# Generated deterministically by seda-macro-lef-normalizer-v1; recipe orfs-asap7-fakeram-m4-v1.
VERSION 5.8 ;
BUSBITCHARS "[]" ;
DIVIDERCHAR "/" ;

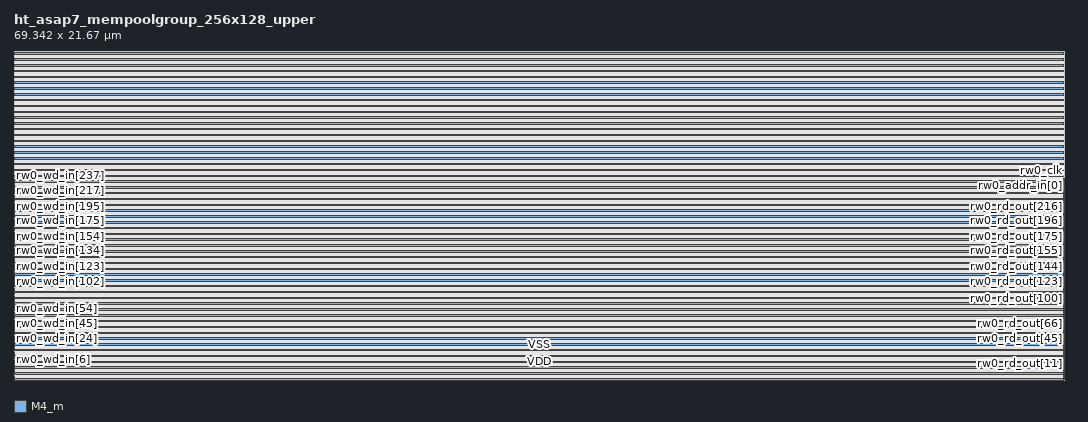
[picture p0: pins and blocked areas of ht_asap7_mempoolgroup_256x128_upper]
MACRO ht_asap7_mempoolgroup_256x128_upper
  FOREIGN ht_asap7_mempoolgroup_256x128_upper 0 0 ;
  CLASS BLOCK ;
  ORIGIN 0 0 ;
  SIZE 69.342 BY 21.67 ;
  SYMMETRY X Y R90 ;
  PIN rw0_wmask_in[0]
    DIRECTION INPUT ;
    USE SIGNAL ;
    SHAPE ABUTMENT ;
    PORT
      LAYER M4_m ;
      RECT 0 0.048 0.024 0.072 ;
    END
  END rw0_wmask_in[0]
  PIN rw0_wmask_in[1]
    DIRECTION INPUT ;
    USE SIGNAL ;
    SHAPE ABUTMENT ;
    PORT
      LAYER M4_m ;
      RECT 0 0.096 0.024 0.12 ;
    END
  END rw0_wmask_in[1]
  PIN rw0_wmask_in[2]
    DIRECTION INPUT ;
    USE SIGNAL ;
    SHAPE ABUTMENT ;
    PORT
      LAYER M4_m ;
      RECT 0 0.144 0.024 0.168 ;
    END
  END rw0_wmask_in[2]
  PIN rw0_wmask_in[3]
    DIRECTION INPUT ;
    USE SIGNAL ;
    SHAPE ABUTMENT ;
    PORT
      LAYER M4_m ;
      RECT 0 0.192 0.024 0.216 ;
    END
  END rw0_wmask_in[3]
  PIN rw0_wmask_in[4]
    DIRECTION INPUT ;
    USE SIGNAL ;
    SHAPE ABUTMENT ;
    PORT
      LAYER M4_m ;
      RECT 0 0.24 0.024 0.264 ;
    END
  END rw0_wmask_in[4]
  PIN rw0_wmask_in[5]
    DIRECTION INPUT ;
    USE SIGNAL ;
    SHAPE ABUTMENT ;
    PORT
      LAYER M4_m ;
      RECT 0 0.288 0.024 0.312 ;
    END
  END rw0_wmask_in[5]
  PIN rw0_wmask_in[6]
    DIRECTION INPUT ;
    USE SIGNAL ;
    SHAPE ABUTMENT ;
    PORT
      LAYER M4_m ;
      RECT 0 0.336 0.024 0.36 ;
    END
  END rw0_wmask_in[6]
  PIN rw0_wmask_in[7]
    DIRECTION INPUT ;
    USE SIGNAL ;
    SHAPE ABUTMENT ;
    PORT
      LAYER M4_m ;
      RECT 0 0.384 0.024 0.408 ;
    END
  END rw0_wmask_in[7]
  PIN rw0_wmask_in[8]
    DIRECTION INPUT ;
    USE SIGNAL ;
    SHAPE ABUTMENT ;
    PORT
      LAYER M4_m ;
      RECT 0 0.432 0.024 0.456 ;
    END
  END rw0_wmask_in[8]
  PIN rw0_wmask_in[9]
    DIRECTION INPUT ;
    USE SIGNAL ;
    SHAPE ABUTMENT ;
    PORT
      LAYER M4_m ;
      RECT 0 0.48 0.024 0.504 ;
    END
  END rw0_wmask_in[9]
  PIN rw0_wmask_in[10]
    DIRECTION INPUT ;
    USE SIGNAL ;
    SHAPE ABUTMENT ;
    PORT
      LAYER M4_m ;
      RECT 0 0.528 0.024 0.552 ;
    END
  END rw0_wmask_in[10]
  PIN rw0_wmask_in[11]
    DIRECTION INPUT ;
    USE SIGNAL ;
    SHAPE ABUTMENT ;
    PORT
      LAYER M4_m ;
      RECT 0 0.576 0.024 0.6 ;
    END
  END rw0_wmask_in[11]
  PIN rw0_wmask_in[12]
    DIRECTION INPUT ;
    USE SIGNAL ;
    SHAPE ABUTMENT ;
    PORT
      LAYER M4_m ;
      RECT 0 0.624 0.024 0.648 ;
    END
  END rw0_wmask_in[12]
  PIN rw0_wmask_in[13]
    DIRECTION INPUT ;
    USE SIGNAL ;
    SHAPE ABUTMENT ;
    PORT
      LAYER M4_m ;
      RECT 0 0.672 0.024 0.696 ;
    END
  END rw0_wmask_in[13]
  PIN rw0_wmask_in[14]
    DIRECTION INPUT ;
    USE SIGNAL ;
    SHAPE ABUTMENT ;
    PORT
      LAYER M4_m ;
      RECT 0 0.72 0.024 0.744 ;
    END
  END rw0_wmask_in[14]
  PIN rw0_wmask_in[15]
    DIRECTION INPUT ;
    USE SIGNAL ;
    SHAPE ABUTMENT ;
    PORT
      LAYER M4_m ;
      RECT 0 0.768 0.024 0.792 ;
    END
  END rw0_wmask_in[15]
  PIN rw0_wmask_in[16]
    DIRECTION INPUT ;
    USE SIGNAL ;
    SHAPE ABUTMENT ;
    PORT
      LAYER M4_m ;
      RECT 0 0.816 0.024 0.84 ;
    END
  END rw0_wmask_in[16]
  PIN rw0_wmask_in[17]
    DIRECTION INPUT ;
    USE SIGNAL ;
    SHAPE ABUTMENT ;
    PORT
      LAYER M4_m ;
      RECT 0 0.864 0.024 0.888 ;
    END
  END rw0_wmask_in[17]
  PIN rw0_wmask_in[18]
    DIRECTION INPUT ;
    USE SIGNAL ;
    SHAPE ABUTMENT ;
    PORT
      LAYER M4_m ;
      RECT 0 0.912 0.024 0.936 ;
    END
  END rw0_wmask_in[18]
  PIN rw0_wmask_in[19]
    DIRECTION INPUT ;
    USE SIGNAL ;
    SHAPE ABUTMENT ;
    PORT
      LAYER M4_m ;
      RECT 0 0.96 0.024 0.984 ;
    END
  END rw0_wmask_in[19]
  PIN rw0_wmask_in[20]
    DIRECTION INPUT ;
    USE SIGNAL ;
    SHAPE ABUTMENT ;
    PORT
      LAYER M4_m ;
      RECT 0 1.008 0.024 1.032 ;
    END
  END rw0_wmask_in[20]
  PIN rw0_wmask_in[21]
    DIRECTION INPUT ;
    USE SIGNAL ;
    SHAPE ABUTMENT ;
    PORT
      LAYER M4_m ;
      RECT 0 1.056 0.024 1.08 ;
    END
  END rw0_wmask_in[21]
  PIN rw0_wmask_in[22]
    DIRECTION INPUT ;
    USE SIGNAL ;
    SHAPE ABUTMENT ;
    PORT
      LAYER M4_m ;
      RECT 0 1.104 0.024 1.128 ;
    END
  END rw0_wmask_in[22]
  PIN rw0_wmask_in[23]
    DIRECTION INPUT ;
    USE SIGNAL ;
    SHAPE ABUTMENT ;
    PORT
      LAYER M4_m ;
      RECT 0 1.152 0.024 1.176 ;
    END
  END rw0_wmask_in[23]
  PIN rw0_wmask_in[24]
    DIRECTION INPUT ;
    USE SIGNAL ;
    SHAPE ABUTMENT ;
    PORT
      LAYER M4_m ;
      RECT 0 1.2 0.024 1.224 ;
    END
  END rw0_wmask_in[24]
  PIN rw0_wmask_in[25]
    DIRECTION INPUT ;
    USE SIGNAL ;
    SHAPE ABUTMENT ;
    PORT
      LAYER M4_m ;
      RECT 0 1.248 0.024 1.272 ;
    END
  END rw0_wmask_in[25]
  PIN rw0_wmask_in[26]
    DIRECTION INPUT ;
    USE SIGNAL ;
    SHAPE ABUTMENT ;
    PORT
      LAYER M4_m ;
      RECT 0 1.296 0.024 1.32 ;
    END
  END rw0_wmask_in[26]
  PIN rw0_wmask_in[27]
    DIRECTION INPUT ;
    USE SIGNAL ;
    SHAPE ABUTMENT ;
    PORT
      LAYER M4_m ;
      RECT 0 1.344 0.024 1.368 ;
    END
  END rw0_wmask_in[27]
  PIN rw0_wmask_in[28]
    DIRECTION INPUT ;
    USE SIGNAL ;
    SHAPE ABUTMENT ;
    PORT
      LAYER M4_m ;
      RECT 0 1.392 0.024 1.416 ;
    END
  END rw0_wmask_in[28]
  PIN rw0_wmask_in[29]
    DIRECTION INPUT ;
    USE SIGNAL ;
    SHAPE ABUTMENT ;
    PORT
      LAYER M4_m ;
      RECT 0 1.44 0.024 1.464 ;
    END
  END rw0_wmask_in[29]
  PIN rw0_wmask_in[30]
    DIRECTION INPUT ;
    USE SIGNAL ;
    SHAPE ABUTMENT ;
    PORT
      LAYER M4_m ;
      RECT 0 1.488 0.024 1.512 ;
    END
  END rw0_wmask_in[30]
  PIN rw0_wmask_in[31]
    DIRECTION INPUT ;
    USE SIGNAL ;
    SHAPE ABUTMENT ;
    PORT
      LAYER M4_m ;
      RECT 0 1.536 0.024 1.56 ;
    END
  END rw0_wmask_in[31]
  PIN rw0_wd_in[0]
    DIRECTION INPUT ;
    USE SIGNAL ;
    SHAPE ABUTMENT ;
    PORT
      LAYER M4_m ;
      RECT 0 1.584 0.024 1.608 ;
    END
  END rw0_wd_in[0]
  PIN rw0_wd_in[1]
    DIRECTION INPUT ;
    USE SIGNAL ;
    SHAPE ABUTMENT ;
    PORT
      LAYER M4_m ;
      RECT 0 1.632 0.024 1.656 ;
    END
  END rw0_wd_in[1]
  PIN rw0_wd_in[2]
    DIRECTION INPUT ;
    USE SIGNAL ;
    SHAPE ABUTMENT ;
    PORT
      LAYER M4_m ;
      RECT 0 1.68 0.024 1.704 ;
    END
  END rw0_wd_in[2]
  PIN rw0_wd_in[3]
    DIRECTION INPUT ;
    USE SIGNAL ;
    SHAPE ABUTMENT ;
    PORT
      LAYER M4_m ;
      RECT 0 1.728 0.024 1.752 ;
    END
  END rw0_wd_in[3]
  PIN rw0_wd_in[4]
    DIRECTION INPUT ;
    USE SIGNAL ;
    SHAPE ABUTMENT ;
    PORT
      LAYER M4_m ;
      RECT 0 1.776 0.024 1.8 ;
    END
  END rw0_wd_in[4]
  PIN rw0_wd_in[5]
    DIRECTION INPUT ;
    USE SIGNAL ;
    SHAPE ABUTMENT ;
    PORT
      LAYER M4_m ;
      RECT 0 1.824 0.024 1.848 ;
    END
  END rw0_wd_in[5]
  PIN rw0_wd_in[6]
    DIRECTION INPUT ;
    USE SIGNAL ;
    SHAPE ABUTMENT ;
    PORT
      LAYER M4_m ;
      RECT 0 1.872 0.024 1.896 ;
    END
  END rw0_wd_in[6]
  PIN rw0_wd_in[7]
    DIRECTION INPUT ;
    USE SIGNAL ;
    SHAPE ABUTMENT ;
    PORT
      LAYER M4_m ;
      RECT 0 1.92 0.024 1.944 ;
    END
  END rw0_wd_in[7]
  PIN rw0_wd_in[8]
    DIRECTION INPUT ;
    USE SIGNAL ;
    SHAPE ABUTMENT ;
    PORT
      LAYER M4_m ;
      RECT 0 1.968 0.024 1.992 ;
    END
  END rw0_wd_in[8]
  PIN rw0_wd_in[9]
    DIRECTION INPUT ;
    USE SIGNAL ;
    SHAPE ABUTMENT ;
    PORT
      LAYER M4_m ;
      RECT 0 2.016 0.024 2.04 ;
    END
  END rw0_wd_in[9]
  PIN rw0_wd_in[10]
    DIRECTION INPUT ;
    USE SIGNAL ;
    SHAPE ABUTMENT ;
    PORT
      LAYER M4_m ;
      RECT 0 2.064 0.024 2.088 ;
    END
  END rw0_wd_in[10]
  PIN rw0_wd_in[11]
    DIRECTION INPUT ;
    USE SIGNAL ;
    SHAPE ABUTMENT ;
    PORT
      LAYER M4_m ;
      RECT 0 2.112 0.024 2.136 ;
    END
  END rw0_wd_in[11]
  PIN rw0_wd_in[12]
    DIRECTION INPUT ;
    USE SIGNAL ;
    SHAPE ABUTMENT ;
    PORT
      LAYER M4_m ;
      RECT 0 2.16 0.024 2.184 ;
    END
  END rw0_wd_in[12]
  PIN rw0_wd_in[13]
    DIRECTION INPUT ;
    USE SIGNAL ;
    SHAPE ABUTMENT ;
    PORT
      LAYER M4_m ;
      RECT 0 2.208 0.024 2.232 ;
    END
  END rw0_wd_in[13]
  PIN rw0_wd_in[14]
    DIRECTION INPUT ;
    USE SIGNAL ;
    SHAPE ABUTMENT ;
    PORT
      LAYER M4_m ;
      RECT 0 2.256 0.024 2.28 ;
    END
  END rw0_wd_in[14]
  PIN rw0_wd_in[15]
    DIRECTION INPUT ;
    USE SIGNAL ;
    SHAPE ABUTMENT ;
    PORT
      LAYER M4_m ;
      RECT 0 2.304 0.024 2.328 ;
    END
  END rw0_wd_in[15]
  PIN rw0_wd_in[16]
    DIRECTION INPUT ;
    USE SIGNAL ;
    SHAPE ABUTMENT ;
    PORT
      LAYER M4_m ;
      RECT 0 2.352 0.024 2.376 ;
    END
  END rw0_wd_in[16]
  PIN rw0_wd_in[17]
    DIRECTION INPUT ;
    USE SIGNAL ;
    SHAPE ABUTMENT ;
    PORT
      LAYER M4_m ;
      RECT 0 2.4 0.024 2.424 ;
    END
  END rw0_wd_in[17]
  PIN rw0_wd_in[18]
    DIRECTION INPUT ;
    USE SIGNAL ;
    SHAPE ABUTMENT ;
    PORT
      LAYER M4_m ;
      RECT 0 2.448 0.024 2.472 ;
    END
  END rw0_wd_in[18]
  PIN rw0_wd_in[19]
    DIRECTION INPUT ;
    USE SIGNAL ;
    SHAPE ABUTMENT ;
    PORT
      LAYER M4_m ;
      RECT 0 2.496 0.024 2.52 ;
    END
  END rw0_wd_in[19]
  PIN rw0_wd_in[20]
    DIRECTION INPUT ;
    USE SIGNAL ;
    SHAPE ABUTMENT ;
    PORT
      LAYER M4_m ;
      RECT 0 2.544 0.024 2.568 ;
    END
  END rw0_wd_in[20]
  PIN rw0_wd_in[21]
    DIRECTION INPUT ;
    USE SIGNAL ;
    SHAPE ABUTMENT ;
    PORT
      LAYER M4_m ;
      RECT 0 2.592 0.024 2.616 ;
    END
  END rw0_wd_in[21]
  PIN rw0_wd_in[22]
    DIRECTION INPUT ;
    USE SIGNAL ;
    SHAPE ABUTMENT ;
    PORT
      LAYER M4_m ;
      RECT 0 2.64 0.024 2.664 ;
    END
  END rw0_wd_in[22]
  PIN rw0_wd_in[23]
    DIRECTION INPUT ;
    USE SIGNAL ;
    SHAPE ABUTMENT ;
    PORT
      LAYER M4_m ;
      RECT 0 2.688 0.024 2.712 ;
    END
  END rw0_wd_in[23]
  PIN rw0_wd_in[24]
    DIRECTION INPUT ;
    USE SIGNAL ;
    SHAPE ABUTMENT ;
    PORT
      LAYER M4_m ;
      RECT 0 2.736 0.024 2.76 ;
    END
  END rw0_wd_in[24]
  PIN rw0_wd_in[25]
    DIRECTION INPUT ;
    USE SIGNAL ;
    SHAPE ABUTMENT ;
    PORT
      LAYER M4_m ;
      RECT 0 2.784 0.024 2.808 ;
    END
  END rw0_wd_in[25]
  PIN rw0_wd_in[26]
    DIRECTION INPUT ;
    USE SIGNAL ;
    SHAPE ABUTMENT ;
    PORT
      LAYER M4_m ;
      RECT 0 2.832 0.024 2.856 ;
    END
  END rw0_wd_in[26]
  PIN rw0_wd_in[27]
    DIRECTION INPUT ;
    USE SIGNAL ;
    SHAPE ABUTMENT ;
    PORT
      LAYER M4_m ;
      RECT 0 2.88 0.024 2.904 ;
    END
  END rw0_wd_in[27]
  PIN rw0_wd_in[28]
    DIRECTION INPUT ;
    USE SIGNAL ;
    SHAPE ABUTMENT ;
    PORT
      LAYER M4_m ;
      RECT 0 2.928 0.024 2.952 ;
    END
  END rw0_wd_in[28]
  PIN rw0_wd_in[29]
    DIRECTION INPUT ;
    USE SIGNAL ;
    SHAPE ABUTMENT ;
    PORT
      LAYER M4_m ;
      RECT 0 2.976 0.024 3 ;
    END
  END rw0_wd_in[29]
  PIN rw0_wd_in[30]
    DIRECTION INPUT ;
    USE SIGNAL ;
    SHAPE ABUTMENT ;
    PORT
      LAYER M4_m ;
      RECT 0 3.024 0.024 3.048 ;
    END
  END rw0_wd_in[30]
  PIN rw0_wd_in[31]
    DIRECTION INPUT ;
    USE SIGNAL ;
    SHAPE ABUTMENT ;
    PORT
      LAYER M4_m ;
      RECT 0 3.072 0.024 3.096 ;
    END
  END rw0_wd_in[31]
  PIN rw0_wd_in[32]
    DIRECTION INPUT ;
    USE SIGNAL ;
    SHAPE ABUTMENT ;
    PORT
      LAYER M4_m ;
      RECT 0 3.12 0.024 3.144 ;
    END
  END rw0_wd_in[32]
  PIN rw0_wd_in[33]
    DIRECTION INPUT ;
    USE SIGNAL ;
    SHAPE ABUTMENT ;
    PORT
      LAYER M4_m ;
      RECT 0 3.168 0.024 3.192 ;
    END
  END rw0_wd_in[33]
  PIN rw0_wd_in[34]
    DIRECTION INPUT ;
    USE SIGNAL ;
    SHAPE ABUTMENT ;
    PORT
      LAYER M4_m ;
      RECT 0 3.216 0.024 3.24 ;
    END
  END rw0_wd_in[34]
  PIN rw0_wd_in[35]
    DIRECTION INPUT ;
    USE SIGNAL ;
    SHAPE ABUTMENT ;
    PORT
      LAYER M4_m ;
      RECT 0 3.264 0.024 3.288 ;
    END
  END rw0_wd_in[35]
  PIN rw0_wd_in[36]
    DIRECTION INPUT ;
    USE SIGNAL ;
    SHAPE ABUTMENT ;
    PORT
      LAYER M4_m ;
      RECT 0 3.312 0.024 3.336 ;
    END
  END rw0_wd_in[36]
  PIN rw0_wd_in[37]
    DIRECTION INPUT ;
    USE SIGNAL ;
    SHAPE ABUTMENT ;
    PORT
      LAYER M4_m ;
      RECT 0 3.36 0.024 3.384 ;
    END
  END rw0_wd_in[37]
  PIN rw0_wd_in[38]
    DIRECTION INPUT ;
    USE SIGNAL ;
    SHAPE ABUTMENT ;
    PORT
      LAYER M4_m ;
      RECT 0 3.408 0.024 3.432 ;
    END
  END rw0_wd_in[38]
  PIN rw0_wd_in[39]
    DIRECTION INPUT ;
    USE SIGNAL ;
    SHAPE ABUTMENT ;
    PORT
      LAYER M4_m ;
      RECT 0 3.456 0.024 3.48 ;
    END
  END rw0_wd_in[39]
  PIN rw0_wd_in[40]
    DIRECTION INPUT ;
    USE SIGNAL ;
    SHAPE ABUTMENT ;
    PORT
      LAYER M4_m ;
      RECT 0 3.504 0.024 3.528 ;
    END
  END rw0_wd_in[40]
  PIN rw0_wd_in[41]
    DIRECTION INPUT ;
    USE SIGNAL ;
    SHAPE ABUTMENT ;
    PORT
      LAYER M4_m ;
      RECT 0 3.552 0.024 3.576 ;
    END
  END rw0_wd_in[41]
  PIN rw0_wd_in[42]
    DIRECTION INPUT ;
    USE SIGNAL ;
    SHAPE ABUTMENT ;
    PORT
      LAYER M4_m ;
      RECT 0 3.6 0.024 3.624 ;
    END
  END rw0_wd_in[42]
  PIN rw0_wd_in[43]
    DIRECTION INPUT ;
    USE SIGNAL ;
    SHAPE ABUTMENT ;
    PORT
      LAYER M4_m ;
      RECT 0 3.648 0.024 3.672 ;
    END
  END rw0_wd_in[43]
  PIN rw0_wd_in[44]
    DIRECTION INPUT ;
    USE SIGNAL ;
    SHAPE ABUTMENT ;
    PORT
      LAYER M4_m ;
      RECT 0 3.696 0.024 3.72 ;
    END
  END rw0_wd_in[44]
  PIN rw0_wd_in[45]
    DIRECTION INPUT ;
    USE SIGNAL ;
    SHAPE ABUTMENT ;
    PORT
      LAYER M4_m ;
      RECT 0 3.744 0.024 3.768 ;
    END
  END rw0_wd_in[45]
  PIN rw0_wd_in[46]
    DIRECTION INPUT ;
    USE SIGNAL ;
    SHAPE ABUTMENT ;
    PORT
      LAYER M4_m ;
      RECT 0 3.792 0.024 3.816 ;
    END
  END rw0_wd_in[46]
  PIN rw0_wd_in[47]
    DIRECTION INPUT ;
    USE SIGNAL ;
    SHAPE ABUTMENT ;
    PORT
      LAYER M4_m ;
      RECT 0 3.84 0.024 3.864 ;
    END
  END rw0_wd_in[47]
  PIN rw0_wd_in[48]
    DIRECTION INPUT ;
    USE SIGNAL ;
    SHAPE ABUTMENT ;
    PORT
      LAYER M4_m ;
      RECT 0 3.888 0.024 3.912 ;
    END
  END rw0_wd_in[48]
  PIN rw0_wd_in[49]
    DIRECTION INPUT ;
    USE SIGNAL ;
    SHAPE ABUTMENT ;
    PORT
      LAYER M4_m ;
      RECT 0 3.936 0.024 3.96 ;
    END
  END rw0_wd_in[49]
  PIN rw0_wd_in[50]
    DIRECTION INPUT ;
    USE SIGNAL ;
    SHAPE ABUTMENT ;
    PORT
      LAYER M4_m ;
      RECT 0 3.984 0.024 4.008 ;
    END
  END rw0_wd_in[50]
  PIN rw0_wd_in[51]
    DIRECTION INPUT ;
    USE SIGNAL ;
    SHAPE ABUTMENT ;
    PORT
      LAYER M4_m ;
      RECT 0 4.032 0.024 4.056 ;
    END
  END rw0_wd_in[51]
  PIN rw0_wd_in[52]
    DIRECTION INPUT ;
    USE SIGNAL ;
    SHAPE ABUTMENT ;
    PORT
      LAYER M4_m ;
      RECT 0 4.08 0.024 4.104 ;
    END
  END rw0_wd_in[52]
  PIN rw0_wd_in[53]
    DIRECTION INPUT ;
    USE SIGNAL ;
    SHAPE ABUTMENT ;
    PORT
      LAYER M4_m ;
      RECT 0 4.128 0.024 4.152 ;
    END
  END rw0_wd_in[53]
  PIN rw0_wd_in[54]
    DIRECTION INPUT ;
    USE SIGNAL ;
    SHAPE ABUTMENT ;
    PORT
      LAYER M4_m ;
      RECT 0 4.176 0.024 4.2 ;
    END
  END rw0_wd_in[54]
  PIN rw0_wd_in[55]
    DIRECTION INPUT ;
    USE SIGNAL ;
    SHAPE ABUTMENT ;
    PORT
      LAYER M4_m ;
      RECT 0 4.224 0.024 4.248 ;
    END
  END rw0_wd_in[55]
  PIN rw0_wd_in[56]
    DIRECTION INPUT ;
    USE SIGNAL ;
    SHAPE ABUTMENT ;
    PORT
      LAYER M4_m ;
      RECT 0 4.272 0.024 4.296 ;
    END
  END rw0_wd_in[56]
  PIN rw0_wd_in[57]
    DIRECTION INPUT ;
    USE SIGNAL ;
    SHAPE ABUTMENT ;
    PORT
      LAYER M4_m ;
      RECT 0 4.32 0.024 4.344 ;
    END
  END rw0_wd_in[57]
  PIN rw0_wd_in[58]
    DIRECTION INPUT ;
    USE SIGNAL ;
    SHAPE ABUTMENT ;
    PORT
      LAYER M4_m ;
      RECT 0 4.368 0.024 4.392 ;
    END
  END rw0_wd_in[58]
  PIN rw0_wd_in[59]
    DIRECTION INPUT ;
    USE SIGNAL ;
    SHAPE ABUTMENT ;
    PORT
      LAYER M4_m ;
      RECT 0 4.416 0.024 4.44 ;
    END
  END rw0_wd_in[59]
  PIN rw0_wd_in[60]
    DIRECTION INPUT ;
    USE SIGNAL ;
    SHAPE ABUTMENT ;
    PORT
      LAYER M4_m ;
      RECT 0 4.464 0.024 4.488 ;
    END
  END rw0_wd_in[60]
  PIN rw0_wd_in[61]
    DIRECTION INPUT ;
    USE SIGNAL ;
    SHAPE ABUTMENT ;
    PORT
      LAYER M4_m ;
      RECT 0 4.512 0.024 4.536 ;
    END
  END rw0_wd_in[61]
  PIN rw0_wd_in[62]
    DIRECTION INPUT ;
    USE SIGNAL ;
    SHAPE ABUTMENT ;
    PORT
      LAYER M4_m ;
      RECT 0 4.56 0.024 4.584 ;
    END
  END rw0_wd_in[62]
  PIN rw0_wd_in[63]
    DIRECTION INPUT ;
    USE SIGNAL ;
    SHAPE ABUTMENT ;
    PORT
      LAYER M4_m ;
      RECT 0 4.608 0.024 4.632 ;
    END
  END rw0_wd_in[63]
  PIN rw0_wd_in[64]
    DIRECTION INPUT ;
    USE SIGNAL ;
    SHAPE ABUTMENT ;
    PORT
      LAYER M4_m ;
      RECT 0 4.656 0.024 4.68 ;
    END
  END rw0_wd_in[64]
  PIN rw0_wd_in[65]
    DIRECTION INPUT ;
    USE SIGNAL ;
    SHAPE ABUTMENT ;
    PORT
      LAYER M4_m ;
      RECT 0 4.704 0.024 4.728 ;
    END
  END rw0_wd_in[65]
  PIN rw0_wd_in[66]
    DIRECTION INPUT ;
    USE SIGNAL ;
    SHAPE ABUTMENT ;
    PORT
      LAYER M4_m ;
      RECT 0 4.752 0.024 4.776 ;
    END
  END rw0_wd_in[66]
  PIN rw0_wd_in[67]
    DIRECTION INPUT ;
    USE SIGNAL ;
    SHAPE ABUTMENT ;
    PORT
      LAYER M4_m ;
      RECT 0 4.8 0.024 4.824 ;
    END
  END rw0_wd_in[67]
  PIN rw0_wd_in[68]
    DIRECTION INPUT ;
    USE SIGNAL ;
    SHAPE ABUTMENT ;
    PORT
      LAYER M4_m ;
      RECT 0 4.848 0.024 4.872 ;
    END
  END rw0_wd_in[68]
  PIN rw0_wd_in[69]
    DIRECTION INPUT ;
    USE SIGNAL ;
    SHAPE ABUTMENT ;
    PORT
      LAYER M4_m ;
      RECT 0 4.896 0.024 4.92 ;
    END
  END rw0_wd_in[69]
  PIN rw0_wd_in[70]
    DIRECTION INPUT ;
    USE SIGNAL ;
    SHAPE ABUTMENT ;
    PORT
      LAYER M4_m ;
      RECT 0 4.944 0.024 4.968 ;
    END
  END rw0_wd_in[70]
  PIN rw0_wd_in[71]
    DIRECTION INPUT ;
    USE SIGNAL ;
    SHAPE ABUTMENT ;
    PORT
      LAYER M4_m ;
      RECT 0 4.992 0.024 5.016 ;
    END
  END rw0_wd_in[71]
  PIN rw0_wd_in[72]
    DIRECTION INPUT ;
    USE SIGNAL ;
    SHAPE ABUTMENT ;
    PORT
      LAYER M4_m ;
      RECT 0 5.04 0.024 5.064 ;
    END
  END rw0_wd_in[72]
  PIN rw0_wd_in[73]
    DIRECTION INPUT ;
    USE SIGNAL ;
    SHAPE ABUTMENT ;
    PORT
      LAYER M4_m ;
      RECT 0 5.088 0.024 5.112 ;
    END
  END rw0_wd_in[73]
  PIN rw0_wd_in[74]
    DIRECTION INPUT ;
    USE SIGNAL ;
    SHAPE ABUTMENT ;
    PORT
      LAYER M4_m ;
      RECT 0 5.136 0.024 5.16 ;
    END
  END rw0_wd_in[74]
  PIN rw0_wd_in[75]
    DIRECTION INPUT ;
    USE SIGNAL ;
    SHAPE ABUTMENT ;
    PORT
      LAYER M4_m ;
      RECT 0 5.184 0.024 5.208 ;
    END
  END rw0_wd_in[75]
  PIN rw0_wd_in[76]
    DIRECTION INPUT ;
    USE SIGNAL ;
    SHAPE ABUTMENT ;
    PORT
      LAYER M4_m ;
      RECT 0 5.232 0.024 5.256 ;
    END
  END rw0_wd_in[76]
  PIN rw0_wd_in[77]
    DIRECTION INPUT ;
    USE SIGNAL ;
    SHAPE ABUTMENT ;
    PORT
      LAYER M4_m ;
      RECT 0 5.28 0.024 5.304 ;
    END
  END rw0_wd_in[77]
  PIN rw0_wd_in[78]
    DIRECTION INPUT ;
    USE SIGNAL ;
    SHAPE ABUTMENT ;
    PORT
      LAYER M4_m ;
      RECT 0 5.328 0.024 5.352 ;
    END
  END rw0_wd_in[78]
  PIN rw0_wd_in[79]
    DIRECTION INPUT ;
    USE SIGNAL ;
    SHAPE ABUTMENT ;
    PORT
      LAYER M4_m ;
      RECT 0 5.376 0.024 5.4 ;
    END
  END rw0_wd_in[79]
  PIN rw0_wd_in[80]
    DIRECTION INPUT ;
    USE SIGNAL ;
    SHAPE ABUTMENT ;
    PORT
      LAYER M4_m ;
      RECT 0 5.424 0.024 5.448 ;
    END
  END rw0_wd_in[80]
  PIN rw0_wd_in[81]
    DIRECTION INPUT ;
    USE SIGNAL ;
    SHAPE ABUTMENT ;
    PORT
      LAYER M4_m ;
      RECT 0 5.472 0.024 5.496 ;
    END
  END rw0_wd_in[81]
  PIN rw0_wd_in[82]
    DIRECTION INPUT ;
    USE SIGNAL ;
    SHAPE ABUTMENT ;
    PORT
      LAYER M4_m ;
      RECT 0 5.52 0.024 5.544 ;
    END
  END rw0_wd_in[82]
  PIN rw0_wd_in[83]
    DIRECTION INPUT ;
    USE SIGNAL ;
    SHAPE ABUTMENT ;
    PORT
      LAYER M4_m ;
      RECT 0 5.568 0.024 5.592 ;
    END
  END rw0_wd_in[83]
  PIN rw0_wd_in[84]
    DIRECTION INPUT ;
    USE SIGNAL ;
    SHAPE ABUTMENT ;
    PORT
      LAYER M4_m ;
      RECT 0 5.616 0.024 5.64 ;
    END
  END rw0_wd_in[84]
  PIN rw0_wd_in[85]
    DIRECTION INPUT ;
    USE SIGNAL ;
    SHAPE ABUTMENT ;
    PORT
      LAYER M4_m ;
      RECT 0 5.664 0.024 5.688 ;
    END
  END rw0_wd_in[85]
  PIN rw0_wd_in[86]
    DIRECTION INPUT ;
    USE SIGNAL ;
    SHAPE ABUTMENT ;
    PORT
      LAYER M4_m ;
      RECT 0 5.712 0.024 5.736 ;
    END
  END rw0_wd_in[86]
  PIN rw0_wd_in[87]
    DIRECTION INPUT ;
    USE SIGNAL ;
    SHAPE ABUTMENT ;
    PORT
      LAYER M4_m ;
      RECT 0 5.76 0.024 5.784 ;
    END
  END rw0_wd_in[87]
  PIN rw0_wd_in[88]
    DIRECTION INPUT ;
    USE SIGNAL ;
    SHAPE ABUTMENT ;
    PORT
      LAYER M4_m ;
      RECT 0 5.808 0.024 5.832 ;
    END
  END rw0_wd_in[88]
  PIN rw0_wd_in[89]
    DIRECTION INPUT ;
    USE SIGNAL ;
    SHAPE ABUTMENT ;
    PORT
      LAYER M4_m ;
      RECT 0 5.856 0.024 5.88 ;
    END
  END rw0_wd_in[89]
  PIN rw0_wd_in[90]
    DIRECTION INPUT ;
    USE SIGNAL ;
    SHAPE ABUTMENT ;
    PORT
      LAYER M4_m ;
      RECT 0 5.904 0.024 5.928 ;
    END
  END rw0_wd_in[90]
  PIN rw0_wd_in[91]
    DIRECTION INPUT ;
    USE SIGNAL ;
    SHAPE ABUTMENT ;
    PORT
      LAYER M4_m ;
      RECT 0 5.952 0.024 5.976 ;
    END
  END rw0_wd_in[91]
  PIN rw0_wd_in[92]
    DIRECTION INPUT ;
    USE SIGNAL ;
    SHAPE ABUTMENT ;
    PORT
      LAYER M4_m ;
      RECT 0 6 0.024 6.024 ;
    END
  END rw0_wd_in[92]
  PIN rw0_wd_in[93]
    DIRECTION INPUT ;
    USE SIGNAL ;
    SHAPE ABUTMENT ;
    PORT
      LAYER M4_m ;
      RECT 0 6.048 0.024 6.072 ;
    END
  END rw0_wd_in[93]
  PIN rw0_wd_in[94]
    DIRECTION INPUT ;
    USE SIGNAL ;
    SHAPE ABUTMENT ;
    PORT
      LAYER M4_m ;
      RECT 0 6.096 0.024 6.12 ;
    END
  END rw0_wd_in[94]
  PIN rw0_wd_in[95]
    DIRECTION INPUT ;
    USE SIGNAL ;
    SHAPE ABUTMENT ;
    PORT
      LAYER M4_m ;
      RECT 0 6.144 0.024 6.168 ;
    END
  END rw0_wd_in[95]
  PIN rw0_wd_in[96]
    DIRECTION INPUT ;
    USE SIGNAL ;
    SHAPE ABUTMENT ;
    PORT
      LAYER M4_m ;
      RECT 0 6.192 0.024 6.216 ;
    END
  END rw0_wd_in[96]
  PIN rw0_wd_in[97]
    DIRECTION INPUT ;
    USE SIGNAL ;
    SHAPE ABUTMENT ;
    PORT
      LAYER M4_m ;
      RECT 0 6.24 0.024 6.264 ;
    END
  END rw0_wd_in[97]
  PIN rw0_wd_in[98]
    DIRECTION INPUT ;
    USE SIGNAL ;
    SHAPE ABUTMENT ;
    PORT
      LAYER M4_m ;
      RECT 0 6.288 0.024 6.312 ;
    END
  END rw0_wd_in[98]
  PIN rw0_wd_in[99]
    DIRECTION INPUT ;
    USE SIGNAL ;
    SHAPE ABUTMENT ;
    PORT
      LAYER M4_m ;
      RECT 0 6.336 0.024 6.36 ;
    END
  END rw0_wd_in[99]
  PIN rw0_wd_in[100]
    DIRECTION INPUT ;
    USE SIGNAL ;
    SHAPE ABUTMENT ;
    PORT
      LAYER M4_m ;
      RECT 0 6.384 0.024 6.408 ;
    END
  END rw0_wd_in[100]
  PIN rw0_wd_in[101]
    DIRECTION INPUT ;
    USE SIGNAL ;
    SHAPE ABUTMENT ;
    PORT
      LAYER M4_m ;
      RECT 0 6.432 0.024 6.456 ;
    END
  END rw0_wd_in[101]
  PIN rw0_wd_in[102]
    DIRECTION INPUT ;
    USE SIGNAL ;
    SHAPE ABUTMENT ;
    PORT
      LAYER M4_m ;
      RECT 0 6.48 0.024 6.504 ;
    END
  END rw0_wd_in[102]
  PIN rw0_wd_in[103]
    DIRECTION INPUT ;
    USE SIGNAL ;
    SHAPE ABUTMENT ;
    PORT
      LAYER M4_m ;
      RECT 0 6.528 0.024 6.552 ;
    END
  END rw0_wd_in[103]
  PIN rw0_wd_in[104]
    DIRECTION INPUT ;
    USE SIGNAL ;
    SHAPE ABUTMENT ;
    PORT
      LAYER M4_m ;
      RECT 0 6.576 0.024 6.6 ;
    END
  END rw0_wd_in[104]
  PIN rw0_wd_in[105]
    DIRECTION INPUT ;
    USE SIGNAL ;
    SHAPE ABUTMENT ;
    PORT
      LAYER M4_m ;
      RECT 0 6.624 0.024 6.648 ;
    END
  END rw0_wd_in[105]
  PIN rw0_wd_in[106]
    DIRECTION INPUT ;
    USE SIGNAL ;
    SHAPE ABUTMENT ;
    PORT
      LAYER M4_m ;
      RECT 0 6.672 0.024 6.696 ;
    END
  END rw0_wd_in[106]
  PIN rw0_wd_in[107]
    DIRECTION INPUT ;
    USE SIGNAL ;
    SHAPE ABUTMENT ;
    PORT
      LAYER M4_m ;
      RECT 0 6.72 0.024 6.744 ;
    END
  END rw0_wd_in[107]
  PIN rw0_wd_in[108]
    DIRECTION INPUT ;
    USE SIGNAL ;
    SHAPE ABUTMENT ;
    PORT
      LAYER M4_m ;
      RECT 0 6.768 0.024 6.792 ;
    END
  END rw0_wd_in[108]
  PIN rw0_wd_in[109]
    DIRECTION INPUT ;
    USE SIGNAL ;
    SHAPE ABUTMENT ;
    PORT
      LAYER M4_m ;
      RECT 0 6.816 0.024 6.84 ;
    END
  END rw0_wd_in[109]
  PIN rw0_wd_in[110]
    DIRECTION INPUT ;
    USE SIGNAL ;
    SHAPE ABUTMENT ;
    PORT
      LAYER M4_m ;
      RECT 0 6.864 0.024 6.888 ;
    END
  END rw0_wd_in[110]
  PIN rw0_wd_in[111]
    DIRECTION INPUT ;
    USE SIGNAL ;
    SHAPE ABUTMENT ;
    PORT
      LAYER M4_m ;
      RECT 0 6.912 0.024 6.936 ;
    END
  END rw0_wd_in[111]
  PIN rw0_wd_in[112]
    DIRECTION INPUT ;
    USE SIGNAL ;
    SHAPE ABUTMENT ;
    PORT
      LAYER M4_m ;
      RECT 0 6.96 0.024 6.984 ;
    END
  END rw0_wd_in[112]
  PIN rw0_wd_in[113]
    DIRECTION INPUT ;
    USE SIGNAL ;
    SHAPE ABUTMENT ;
    PORT
      LAYER M4_m ;
      RECT 0 7.008 0.024 7.032 ;
    END
  END rw0_wd_in[113]
  PIN rw0_wd_in[114]
    DIRECTION INPUT ;
    USE SIGNAL ;
    SHAPE ABUTMENT ;
    PORT
      LAYER M4_m ;
      RECT 0 7.056 0.024 7.08 ;
    END
  END rw0_wd_in[114]
  PIN rw0_wd_in[115]
    DIRECTION INPUT ;
    USE SIGNAL ;
    SHAPE ABUTMENT ;
    PORT
      LAYER M4_m ;
      RECT 0 7.104 0.024 7.128 ;
    END
  END rw0_wd_in[115]
  PIN rw0_wd_in[116]
    DIRECTION INPUT ;
    USE SIGNAL ;
    SHAPE ABUTMENT ;
    PORT
      LAYER M4_m ;
      RECT 0 7.152 0.024 7.176 ;
    END
  END rw0_wd_in[116]
  PIN rw0_wd_in[117]
    DIRECTION INPUT ;
    USE SIGNAL ;
    SHAPE ABUTMENT ;
    PORT
      LAYER M4_m ;
      RECT 0 7.2 0.024 7.224 ;
    END
  END rw0_wd_in[117]
  PIN rw0_wd_in[118]
    DIRECTION INPUT ;
    USE SIGNAL ;
    SHAPE ABUTMENT ;
    PORT
      LAYER M4_m ;
      RECT 0 7.248 0.024 7.272 ;
    END
  END rw0_wd_in[118]
  PIN rw0_wd_in[119]
    DIRECTION INPUT ;
    USE SIGNAL ;
    SHAPE ABUTMENT ;
    PORT
      LAYER M4_m ;
      RECT 0 7.296 0.024 7.32 ;
    END
  END rw0_wd_in[119]
  PIN rw0_wd_in[120]
    DIRECTION INPUT ;
    USE SIGNAL ;
    SHAPE ABUTMENT ;
    PORT
      LAYER M4_m ;
      RECT 0 7.344 0.024 7.368 ;
    END
  END rw0_wd_in[120]
  PIN rw0_wd_in[121]
    DIRECTION INPUT ;
    USE SIGNAL ;
    SHAPE ABUTMENT ;
    PORT
      LAYER M4_m ;
      RECT 0 7.392 0.024 7.416 ;
    END
  END rw0_wd_in[121]
  PIN rw0_wd_in[122]
    DIRECTION INPUT ;
    USE SIGNAL ;
    SHAPE ABUTMENT ;
    PORT
      LAYER M4_m ;
      RECT 0 7.44 0.024 7.464 ;
    END
  END rw0_wd_in[122]
  PIN rw0_wd_in[123]
    DIRECTION INPUT ;
    USE SIGNAL ;
    SHAPE ABUTMENT ;
    PORT
      LAYER M4_m ;
      RECT 0 7.488 0.024 7.512 ;
    END
  END rw0_wd_in[123]
  PIN rw0_wd_in[124]
    DIRECTION INPUT ;
    USE SIGNAL ;
    SHAPE ABUTMENT ;
    PORT
      LAYER M4_m ;
      RECT 0 7.536 0.024 7.56 ;
    END
  END rw0_wd_in[124]
  PIN rw0_wd_in[125]
    DIRECTION INPUT ;
    USE SIGNAL ;
    SHAPE ABUTMENT ;
    PORT
      LAYER M4_m ;
      RECT 0 7.584 0.024 7.608 ;
    END
  END rw0_wd_in[125]
  PIN rw0_wd_in[126]
    DIRECTION INPUT ;
    USE SIGNAL ;
    SHAPE ABUTMENT ;
    PORT
      LAYER M4_m ;
      RECT 0 7.632 0.024 7.656 ;
    END
  END rw0_wd_in[126]
  PIN rw0_wd_in[127]
    DIRECTION INPUT ;
    USE SIGNAL ;
    SHAPE ABUTMENT ;
    PORT
      LAYER M4_m ;
      RECT 0 7.68 0.024 7.704 ;
    END
  END rw0_wd_in[127]
  PIN rw0_wd_in[128]
    DIRECTION INPUT ;
    USE SIGNAL ;
    SHAPE ABUTMENT ;
    PORT
      LAYER M4_m ;
      RECT 0 7.728 0.024 7.752 ;
    END
  END rw0_wd_in[128]
  PIN rw0_wd_in[129]
    DIRECTION INPUT ;
    USE SIGNAL ;
    SHAPE ABUTMENT ;
    PORT
      LAYER M4_m ;
      RECT 0 7.776 0.024 7.8 ;
    END
  END rw0_wd_in[129]
  PIN rw0_wd_in[130]
    DIRECTION INPUT ;
    USE SIGNAL ;
    SHAPE ABUTMENT ;
    PORT
      LAYER M4_m ;
      RECT 0 7.824 0.024 7.848 ;
    END
  END rw0_wd_in[130]
  PIN rw0_wd_in[131]
    DIRECTION INPUT ;
    USE SIGNAL ;
    SHAPE ABUTMENT ;
    PORT
      LAYER M4_m ;
      RECT 0 7.872 0.024 7.896 ;
    END
  END rw0_wd_in[131]
  PIN rw0_wd_in[132]
    DIRECTION INPUT ;
    USE SIGNAL ;
    SHAPE ABUTMENT ;
    PORT
      LAYER M4_m ;
      RECT 0 7.92 0.024 7.944 ;
    END
  END rw0_wd_in[132]
  PIN rw0_wd_in[133]
    DIRECTION INPUT ;
    USE SIGNAL ;
    SHAPE ABUTMENT ;
    PORT
      LAYER M4_m ;
      RECT 0 7.968 0.024 7.992 ;
    END
  END rw0_wd_in[133]
  PIN rw0_wd_in[134]
    DIRECTION INPUT ;
    USE SIGNAL ;
    SHAPE ABUTMENT ;
    PORT
      LAYER M4_m ;
      RECT 0 8.016 0.024 8.04 ;
    END
  END rw0_wd_in[134]
  PIN rw0_wd_in[135]
    DIRECTION INPUT ;
    USE SIGNAL ;
    SHAPE ABUTMENT ;
    PORT
      LAYER M4_m ;
      RECT 0 8.064 0.024 8.088 ;
    END
  END rw0_wd_in[135]
  PIN rw0_wd_in[136]
    DIRECTION INPUT ;
    USE SIGNAL ;
    SHAPE ABUTMENT ;
    PORT
      LAYER M4_m ;
      RECT 0 8.112 0.024 8.136 ;
    END
  END rw0_wd_in[136]
  PIN rw0_wd_in[137]
    DIRECTION INPUT ;
    USE SIGNAL ;
    SHAPE ABUTMENT ;
    PORT
      LAYER M4_m ;
      RECT 0 8.16 0.024 8.184 ;
    END
  END rw0_wd_in[137]
  PIN rw0_wd_in[138]
    DIRECTION INPUT ;
    USE SIGNAL ;
    SHAPE ABUTMENT ;
    PORT
      LAYER M4_m ;
      RECT 0 8.208 0.024 8.232 ;
    END
  END rw0_wd_in[138]
  PIN rw0_wd_in[139]
    DIRECTION INPUT ;
    USE SIGNAL ;
    SHAPE ABUTMENT ;
    PORT
      LAYER M4_m ;
      RECT 0 8.256 0.024 8.28 ;
    END
  END rw0_wd_in[139]
  PIN rw0_wd_in[140]
    DIRECTION INPUT ;
    USE SIGNAL ;
    SHAPE ABUTMENT ;
    PORT
      LAYER M4_m ;
      RECT 0 8.304 0.024 8.328 ;
    END
  END rw0_wd_in[140]
  PIN rw0_wd_in[141]
    DIRECTION INPUT ;
    USE SIGNAL ;
    SHAPE ABUTMENT ;
    PORT
      LAYER M4_m ;
      RECT 0 8.352 0.024 8.376 ;
    END
  END rw0_wd_in[141]
  PIN rw0_wd_in[142]
    DIRECTION INPUT ;
    USE SIGNAL ;
    SHAPE ABUTMENT ;
    PORT
      LAYER M4_m ;
      RECT 0 8.4 0.024 8.424 ;
    END
  END rw0_wd_in[142]
  PIN rw0_wd_in[143]
    DIRECTION INPUT ;
    USE SIGNAL ;
    SHAPE ABUTMENT ;
    PORT
      LAYER M4_m ;
      RECT 0 8.448 0.024 8.472 ;
    END
  END rw0_wd_in[143]
  PIN rw0_wd_in[144]
    DIRECTION INPUT ;
    USE SIGNAL ;
    SHAPE ABUTMENT ;
    PORT
      LAYER M4_m ;
      RECT 0 8.496 0.024 8.52 ;
    END
  END rw0_wd_in[144]
  PIN rw0_wd_in[145]
    DIRECTION INPUT ;
    USE SIGNAL ;
    SHAPE ABUTMENT ;
    PORT
      LAYER M4_m ;
      RECT 0 8.544 0.024 8.568 ;
    END
  END rw0_wd_in[145]
  PIN rw0_wd_in[146]
    DIRECTION INPUT ;
    USE SIGNAL ;
    SHAPE ABUTMENT ;
    PORT
      LAYER M4_m ;
      RECT 0 8.592 0.024 8.616 ;
    END
  END rw0_wd_in[146]
  PIN rw0_wd_in[147]
    DIRECTION INPUT ;
    USE SIGNAL ;
    SHAPE ABUTMENT ;
    PORT
      LAYER M4_m ;
      RECT 0 8.64 0.024 8.664 ;
    END
  END rw0_wd_in[147]
  PIN rw0_wd_in[148]
    DIRECTION INPUT ;
    USE SIGNAL ;
    SHAPE ABUTMENT ;
    PORT
      LAYER M4_m ;
      RECT 0 8.688 0.024 8.712 ;
    END
  END rw0_wd_in[148]
  PIN rw0_wd_in[149]
    DIRECTION INPUT ;
    USE SIGNAL ;
    SHAPE ABUTMENT ;
    PORT
      LAYER M4_m ;
      RECT 0 8.736 0.024 8.76 ;
    END
  END rw0_wd_in[149]
  PIN rw0_wd_in[150]
    DIRECTION INPUT ;
    USE SIGNAL ;
    SHAPE ABUTMENT ;
    PORT
      LAYER M4_m ;
      RECT 0 8.784 0.024 8.808 ;
    END
  END rw0_wd_in[150]
  PIN rw0_wd_in[151]
    DIRECTION INPUT ;
    USE SIGNAL ;
    SHAPE ABUTMENT ;
    PORT
      LAYER M4_m ;
      RECT 0 8.832 0.024 8.856 ;
    END
  END rw0_wd_in[151]
  PIN rw0_wd_in[152]
    DIRECTION INPUT ;
    USE SIGNAL ;
    SHAPE ABUTMENT ;
    PORT
      LAYER M4_m ;
      RECT 0 8.88 0.024 8.904 ;
    END
  END rw0_wd_in[152]
  PIN rw0_wd_in[153]
    DIRECTION INPUT ;
    USE SIGNAL ;
    SHAPE ABUTMENT ;
    PORT
      LAYER M4_m ;
      RECT 0 8.928 0.024 8.952 ;
    END
  END rw0_wd_in[153]
  PIN rw0_wd_in[154]
    DIRECTION INPUT ;
    USE SIGNAL ;
    SHAPE ABUTMENT ;
    PORT
      LAYER M4_m ;
      RECT 0 8.976 0.024 9 ;
    END
  END rw0_wd_in[154]
  PIN rw0_wd_in[155]
    DIRECTION INPUT ;
    USE SIGNAL ;
    SHAPE ABUTMENT ;
    PORT
      LAYER M4_m ;
      RECT 0 9.024 0.024 9.048 ;
    END
  END rw0_wd_in[155]
  PIN rw0_wd_in[156]
    DIRECTION INPUT ;
    USE SIGNAL ;
    SHAPE ABUTMENT ;
    PORT
      LAYER M4_m ;
      RECT 0 9.072 0.024 9.096 ;
    END
  END rw0_wd_in[156]
  PIN rw0_wd_in[157]
    DIRECTION INPUT ;
    USE SIGNAL ;
    SHAPE ABUTMENT ;
    PORT
      LAYER M4_m ;
      RECT 0 9.12 0.024 9.144 ;
    END
  END rw0_wd_in[157]
  PIN rw0_wd_in[158]
    DIRECTION INPUT ;
    USE SIGNAL ;
    SHAPE ABUTMENT ;
    PORT
      LAYER M4_m ;
      RECT 0 9.168 0.024 9.192 ;
    END
  END rw0_wd_in[158]
  PIN rw0_wd_in[159]
    DIRECTION INPUT ;
    USE SIGNAL ;
    SHAPE ABUTMENT ;
    PORT
      LAYER M4_m ;
      RECT 0 9.216 0.024 9.24 ;
    END
  END rw0_wd_in[159]
  PIN rw0_wd_in[160]
    DIRECTION INPUT ;
    USE SIGNAL ;
    SHAPE ABUTMENT ;
    PORT
      LAYER M4_m ;
      RECT 0 9.264 0.024 9.288 ;
    END
  END rw0_wd_in[160]
  PIN rw0_wd_in[161]
    DIRECTION INPUT ;
    USE SIGNAL ;
    SHAPE ABUTMENT ;
    PORT
      LAYER M4_m ;
      RECT 0 9.312 0.024 9.336 ;
    END
  END rw0_wd_in[161]
  PIN rw0_wd_in[162]
    DIRECTION INPUT ;
    USE SIGNAL ;
    SHAPE ABUTMENT ;
    PORT
      LAYER M4_m ;
      RECT 0 9.36 0.024 9.384 ;
    END
  END rw0_wd_in[162]
  PIN rw0_wd_in[163]
    DIRECTION INPUT ;
    USE SIGNAL ;
    SHAPE ABUTMENT ;
    PORT
      LAYER M4_m ;
      RECT 0 9.408 0.024 9.432 ;
    END
  END rw0_wd_in[163]
  PIN rw0_wd_in[164]
    DIRECTION INPUT ;
    USE SIGNAL ;
    SHAPE ABUTMENT ;
    PORT
      LAYER M4_m ;
      RECT 0 9.456 0.024 9.48 ;
    END
  END rw0_wd_in[164]
  PIN rw0_wd_in[165]
    DIRECTION INPUT ;
    USE SIGNAL ;
    SHAPE ABUTMENT ;
    PORT
      LAYER M4_m ;
      RECT 0 9.504 0.024 9.528 ;
    END
  END rw0_wd_in[165]
  PIN rw0_wd_in[166]
    DIRECTION INPUT ;
    USE SIGNAL ;
    SHAPE ABUTMENT ;
    PORT
      LAYER M4_m ;
      RECT 0 9.552 0.024 9.576 ;
    END
  END rw0_wd_in[166]
  PIN rw0_wd_in[167]
    DIRECTION INPUT ;
    USE SIGNAL ;
    SHAPE ABUTMENT ;
    PORT
      LAYER M4_m ;
      RECT 0 9.6 0.024 9.624 ;
    END
  END rw0_wd_in[167]
  PIN rw0_wd_in[168]
    DIRECTION INPUT ;
    USE SIGNAL ;
    SHAPE ABUTMENT ;
    PORT
      LAYER M4_m ;
      RECT 0 9.648 0.024 9.672 ;
    END
  END rw0_wd_in[168]
  PIN rw0_wd_in[169]
    DIRECTION INPUT ;
    USE SIGNAL ;
    SHAPE ABUTMENT ;
    PORT
      LAYER M4_m ;
      RECT 0 9.696 0.024 9.72 ;
    END
  END rw0_wd_in[169]
  PIN rw0_wd_in[170]
    DIRECTION INPUT ;
    USE SIGNAL ;
    SHAPE ABUTMENT ;
    PORT
      LAYER M4_m ;
      RECT 0 9.744 0.024 9.768 ;
    END
  END rw0_wd_in[170]
  PIN rw0_wd_in[171]
    DIRECTION INPUT ;
    USE SIGNAL ;
    SHAPE ABUTMENT ;
    PORT
      LAYER M4_m ;
      RECT 0 9.792 0.024 9.816 ;
    END
  END rw0_wd_in[171]
  PIN rw0_wd_in[172]
    DIRECTION INPUT ;
    USE SIGNAL ;
    SHAPE ABUTMENT ;
    PORT
      LAYER M4_m ;
      RECT 0 9.84 0.024 9.864 ;
    END
  END rw0_wd_in[172]
  PIN rw0_wd_in[173]
    DIRECTION INPUT ;
    USE SIGNAL ;
    SHAPE ABUTMENT ;
    PORT
      LAYER M4_m ;
      RECT 0 9.888 0.024 9.912 ;
    END
  END rw0_wd_in[173]
  PIN rw0_wd_in[174]
    DIRECTION INPUT ;
    USE SIGNAL ;
    SHAPE ABUTMENT ;
    PORT
      LAYER M4_m ;
      RECT 0 9.936 0.024 9.96 ;
    END
  END rw0_wd_in[174]
  PIN rw0_wd_in[175]
    DIRECTION INPUT ;
    USE SIGNAL ;
    SHAPE ABUTMENT ;
    PORT
      LAYER M4_m ;
      RECT 0 9.984 0.024 10.008 ;
    END
  END rw0_wd_in[175]
  PIN rw0_wd_in[176]
    DIRECTION INPUT ;
    USE SIGNAL ;
    SHAPE ABUTMENT ;
    PORT
      LAYER M4_m ;
      RECT 0 10.032 0.024 10.056 ;
    END
  END rw0_wd_in[176]
  PIN rw0_wd_in[177]
    DIRECTION INPUT ;
    USE SIGNAL ;
    SHAPE ABUTMENT ;
    PORT
      LAYER M4_m ;
      RECT 0 10.08 0.024 10.104 ;
    END
  END rw0_wd_in[177]
  PIN rw0_wd_in[178]
    DIRECTION INPUT ;
    USE SIGNAL ;
    SHAPE ABUTMENT ;
    PORT
      LAYER M4_m ;
      RECT 0 10.128 0.024 10.152 ;
    END
  END rw0_wd_in[178]
  PIN rw0_wd_in[179]
    DIRECTION INPUT ;
    USE SIGNAL ;
    SHAPE ABUTMENT ;
    PORT
      LAYER M4_m ;
      RECT 0 10.176 0.024 10.2 ;
    END
  END rw0_wd_in[179]
  PIN rw0_wd_in[180]
    DIRECTION INPUT ;
    USE SIGNAL ;
    SHAPE ABUTMENT ;
    PORT
      LAYER M4_m ;
      RECT 0 10.224 0.024 10.248 ;
    END
  END rw0_wd_in[180]
  PIN rw0_wd_in[181]
    DIRECTION INPUT ;
    USE SIGNAL ;
    SHAPE ABUTMENT ;
    PORT
      LAYER M4_m ;
      RECT 0 10.272 0.024 10.296 ;
    END
  END rw0_wd_in[181]
  PIN rw0_wd_in[182]
    DIRECTION INPUT ;
    USE SIGNAL ;
    SHAPE ABUTMENT ;
    PORT
      LAYER M4_m ;
      RECT 0 10.32 0.024 10.344 ;
    END
  END rw0_wd_in[182]
  PIN rw0_wd_in[183]
    DIRECTION INPUT ;
    USE SIGNAL ;
    SHAPE ABUTMENT ;
    PORT
      LAYER M4_m ;
      RECT 0 10.368 0.024 10.392 ;
    END
  END rw0_wd_in[183]
  PIN rw0_wd_in[184]
    DIRECTION INPUT ;
    USE SIGNAL ;
    SHAPE ABUTMENT ;
    PORT
      LAYER M4_m ;
      RECT 0 10.416 0.024 10.44 ;
    END
  END rw0_wd_in[184]
  PIN rw0_wd_in[185]
    DIRECTION INPUT ;
    USE SIGNAL ;
    SHAPE ABUTMENT ;
    PORT
      LAYER M4_m ;
      RECT 0 10.464 0.024 10.488 ;
    END
  END rw0_wd_in[185]
  PIN rw0_wd_in[186]
    DIRECTION INPUT ;
    USE SIGNAL ;
    SHAPE ABUTMENT ;
    PORT
      LAYER M4_m ;
      RECT 0 10.512 0.024 10.536 ;
    END
  END rw0_wd_in[186]
  PIN rw0_wd_in[187]
    DIRECTION INPUT ;
    USE SIGNAL ;
    SHAPE ABUTMENT ;
    PORT
      LAYER M4_m ;
      RECT 0 10.56 0.024 10.584 ;
    END
  END rw0_wd_in[187]
  PIN rw0_wd_in[188]
    DIRECTION INPUT ;
    USE SIGNAL ;
    SHAPE ABUTMENT ;
    PORT
      LAYER M4_m ;
      RECT 0 10.608 0.024 10.632 ;
    END
  END rw0_wd_in[188]
  PIN rw0_wd_in[189]
    DIRECTION INPUT ;
    USE SIGNAL ;
    SHAPE ABUTMENT ;
    PORT
      LAYER M4_m ;
      RECT 0 10.656 0.024 10.68 ;
    END
  END rw0_wd_in[189]
  PIN rw0_wd_in[190]
    DIRECTION INPUT ;
    USE SIGNAL ;
    SHAPE ABUTMENT ;
    PORT
      LAYER M4_m ;
      RECT 0 10.704 0.024 10.728 ;
    END
  END rw0_wd_in[190]
  PIN rw0_wd_in[191]
    DIRECTION INPUT ;
    USE SIGNAL ;
    SHAPE ABUTMENT ;
    PORT
      LAYER M4_m ;
      RECT 0 10.752 0.024 10.776 ;
    END
  END rw0_wd_in[191]
  PIN rw0_wd_in[192]
    DIRECTION INPUT ;
    USE SIGNAL ;
    SHAPE ABUTMENT ;
    PORT
      LAYER M4_m ;
      RECT 0 10.8 0.024 10.824 ;
    END
  END rw0_wd_in[192]
  PIN rw0_wd_in[193]
    DIRECTION INPUT ;
    USE SIGNAL ;
    SHAPE ABUTMENT ;
    PORT
      LAYER M4_m ;
      RECT 0 10.848 0.024 10.872 ;
    END
  END rw0_wd_in[193]
  PIN rw0_wd_in[194]
    DIRECTION INPUT ;
    USE SIGNAL ;
    SHAPE ABUTMENT ;
    PORT
      LAYER M4_m ;
      RECT 0 10.896 0.024 10.92 ;
    END
  END rw0_wd_in[194]
  PIN rw0_wd_in[195]
    DIRECTION INPUT ;
    USE SIGNAL ;
    SHAPE ABUTMENT ;
    PORT
      LAYER M4_m ;
      RECT 0 10.944 0.024 10.968 ;
    END
  END rw0_wd_in[195]
  PIN rw0_wd_in[196]
    DIRECTION INPUT ;
    USE SIGNAL ;
    SHAPE ABUTMENT ;
    PORT
      LAYER M4_m ;
      RECT 0 10.992 0.024 11.016 ;
    END
  END rw0_wd_in[196]
  PIN rw0_wd_in[197]
    DIRECTION INPUT ;
    USE SIGNAL ;
    SHAPE ABUTMENT ;
    PORT
      LAYER M4_m ;
      RECT 0 11.04 0.024 11.064 ;
    END
  END rw0_wd_in[197]
  PIN rw0_wd_in[198]
    DIRECTION INPUT ;
    USE SIGNAL ;
    SHAPE ABUTMENT ;
    PORT
      LAYER M4_m ;
      RECT 0 11.088 0.024 11.112 ;
    END
  END rw0_wd_in[198]
  PIN rw0_wd_in[199]
    DIRECTION INPUT ;
    USE SIGNAL ;
    SHAPE ABUTMENT ;
    PORT
      LAYER M4_m ;
      RECT 0 11.136 0.024 11.16 ;
    END
  END rw0_wd_in[199]
  PIN rw0_wd_in[200]
    DIRECTION INPUT ;
    USE SIGNAL ;
    SHAPE ABUTMENT ;
    PORT
      LAYER M4_m ;
      RECT 0 11.184 0.024 11.208 ;
    END
  END rw0_wd_in[200]
  PIN rw0_wd_in[201]
    DIRECTION INPUT ;
    USE SIGNAL ;
    SHAPE ABUTMENT ;
    PORT
      LAYER M4_m ;
      RECT 0 11.232 0.024 11.256 ;
    END
  END rw0_wd_in[201]
  PIN rw0_wd_in[202]
    DIRECTION INPUT ;
    USE SIGNAL ;
    SHAPE ABUTMENT ;
    PORT
      LAYER M4_m ;
      RECT 0 11.28 0.024 11.304 ;
    END
  END rw0_wd_in[202]
  PIN rw0_wd_in[203]
    DIRECTION INPUT ;
    USE SIGNAL ;
    SHAPE ABUTMENT ;
    PORT
      LAYER M4_m ;
      RECT 0 11.328 0.024 11.352 ;
    END
  END rw0_wd_in[203]
  PIN rw0_wd_in[204]
    DIRECTION INPUT ;
    USE SIGNAL ;
    SHAPE ABUTMENT ;
    PORT
      LAYER M4_m ;
      RECT 0 11.376 0.024 11.4 ;
    END
  END rw0_wd_in[204]
  PIN rw0_wd_in[205]
    DIRECTION INPUT ;
    USE SIGNAL ;
    SHAPE ABUTMENT ;
    PORT
      LAYER M4_m ;
      RECT 0 11.424 0.024 11.448 ;
    END
  END rw0_wd_in[205]
  PIN rw0_wd_in[206]
    DIRECTION INPUT ;
    USE SIGNAL ;
    SHAPE ABUTMENT ;
    PORT
      LAYER M4_m ;
      RECT 0 11.472 0.024 11.496 ;
    END
  END rw0_wd_in[206]
  PIN rw0_wd_in[207]
    DIRECTION INPUT ;
    USE SIGNAL ;
    SHAPE ABUTMENT ;
    PORT
      LAYER M4_m ;
      RECT 0 11.52 0.024 11.544 ;
    END
  END rw0_wd_in[207]
  PIN rw0_wd_in[208]
    DIRECTION INPUT ;
    USE SIGNAL ;
    SHAPE ABUTMENT ;
    PORT
      LAYER M4_m ;
      RECT 0 11.568 0.024 11.592 ;
    END
  END rw0_wd_in[208]
  PIN rw0_wd_in[209]
    DIRECTION INPUT ;
    USE SIGNAL ;
    SHAPE ABUTMENT ;
    PORT
      LAYER M4_m ;
      RECT 0 11.616 0.024 11.64 ;
    END
  END rw0_wd_in[209]
  PIN rw0_wd_in[210]
    DIRECTION INPUT ;
    USE SIGNAL ;
    SHAPE ABUTMENT ;
    PORT
      LAYER M4_m ;
      RECT 0 11.664 0.024 11.688 ;
    END
  END rw0_wd_in[210]
  PIN rw0_wd_in[211]
    DIRECTION INPUT ;
    USE SIGNAL ;
    SHAPE ABUTMENT ;
    PORT
      LAYER M4_m ;
      RECT 0 11.712 0.024 11.736 ;
    END
  END rw0_wd_in[211]
  PIN rw0_wd_in[212]
    DIRECTION INPUT ;
    USE SIGNAL ;
    SHAPE ABUTMENT ;
    PORT
      LAYER M4_m ;
      RECT 0 11.76 0.024 11.784 ;
    END
  END rw0_wd_in[212]
  PIN rw0_wd_in[213]
    DIRECTION INPUT ;
    USE SIGNAL ;
    SHAPE ABUTMENT ;
    PORT
      LAYER M4_m ;
      RECT 0 11.808 0.024 11.832 ;
    END
  END rw0_wd_in[213]
  PIN rw0_wd_in[214]
    DIRECTION INPUT ;
    USE SIGNAL ;
    SHAPE ABUTMENT ;
    PORT
      LAYER M4_m ;
      RECT 0 11.856 0.024 11.88 ;
    END
  END rw0_wd_in[214]
  PIN rw0_wd_in[215]
    DIRECTION INPUT ;
    USE SIGNAL ;
    SHAPE ABUTMENT ;
    PORT
      LAYER M4_m ;
      RECT 0 11.904 0.024 11.928 ;
    END
  END rw0_wd_in[215]
  PIN rw0_wd_in[216]
    DIRECTION INPUT ;
    USE SIGNAL ;
    SHAPE ABUTMENT ;
    PORT
      LAYER M4_m ;
      RECT 0 11.952 0.024 11.976 ;
    END
  END rw0_wd_in[216]
  PIN rw0_wd_in[217]
    DIRECTION INPUT ;
    USE SIGNAL ;
    SHAPE ABUTMENT ;
    PORT
      LAYER M4_m ;
      RECT 0 12 0.024 12.024 ;
    END
  END rw0_wd_in[217]
  PIN rw0_wd_in[218]
    DIRECTION INPUT ;
    USE SIGNAL ;
    SHAPE ABUTMENT ;
    PORT
      LAYER M4_m ;
      RECT 0 12.048 0.024 12.072 ;
    END
  END rw0_wd_in[218]
  PIN rw0_wd_in[219]
    DIRECTION INPUT ;
    USE SIGNAL ;
    SHAPE ABUTMENT ;
    PORT
      LAYER M4_m ;
      RECT 0 12.096 0.024 12.12 ;
    END
  END rw0_wd_in[219]
  PIN rw0_wd_in[220]
    DIRECTION INPUT ;
    USE SIGNAL ;
    SHAPE ABUTMENT ;
    PORT
      LAYER M4_m ;
      RECT 0 12.144 0.024 12.168 ;
    END
  END rw0_wd_in[220]
  PIN rw0_wd_in[221]
    DIRECTION INPUT ;
    USE SIGNAL ;
    SHAPE ABUTMENT ;
    PORT
      LAYER M4_m ;
      RECT 0 12.192 0.024 12.216 ;
    END
  END rw0_wd_in[221]
  PIN rw0_wd_in[222]
    DIRECTION INPUT ;
    USE SIGNAL ;
    SHAPE ABUTMENT ;
    PORT
      LAYER M4_m ;
      RECT 0 12.24 0.024 12.264 ;
    END
  END rw0_wd_in[222]
  PIN rw0_wd_in[223]
    DIRECTION INPUT ;
    USE SIGNAL ;
    SHAPE ABUTMENT ;
    PORT
      LAYER M4_m ;
      RECT 0 12.288 0.024 12.312 ;
    END
  END rw0_wd_in[223]
  PIN rw0_wd_in[224]
    DIRECTION INPUT ;
    USE SIGNAL ;
    SHAPE ABUTMENT ;
    PORT
      LAYER M4_m ;
      RECT 0 12.336 0.024 12.36 ;
    END
  END rw0_wd_in[224]
  PIN rw0_wd_in[225]
    DIRECTION INPUT ;
    USE SIGNAL ;
    SHAPE ABUTMENT ;
    PORT
      LAYER M4_m ;
      RECT 0 12.384 0.024 12.408 ;
    END
  END rw0_wd_in[225]
  PIN rw0_wd_in[226]
    DIRECTION INPUT ;
    USE SIGNAL ;
    SHAPE ABUTMENT ;
    PORT
      LAYER M4_m ;
      RECT 0 12.432 0.024 12.456 ;
    END
  END rw0_wd_in[226]
  PIN rw0_wd_in[227]
    DIRECTION INPUT ;
    USE SIGNAL ;
    SHAPE ABUTMENT ;
    PORT
      LAYER M4_m ;
      RECT 0 12.48 0.024 12.504 ;
    END
  END rw0_wd_in[227]
  PIN rw0_wd_in[228]
    DIRECTION INPUT ;
    USE SIGNAL ;
    SHAPE ABUTMENT ;
    PORT
      LAYER M4_m ;
      RECT 0 12.528 0.024 12.552 ;
    END
  END rw0_wd_in[228]
  PIN rw0_wd_in[229]
    DIRECTION INPUT ;
    USE SIGNAL ;
    SHAPE ABUTMENT ;
    PORT
      LAYER M4_m ;
      RECT 0 12.576 0.024 12.6 ;
    END
  END rw0_wd_in[229]
  PIN rw0_wd_in[230]
    DIRECTION INPUT ;
    USE SIGNAL ;
    SHAPE ABUTMENT ;
    PORT
      LAYER M4_m ;
      RECT 0 12.624 0.024 12.648 ;
    END
  END rw0_wd_in[230]
  PIN rw0_wd_in[231]
    DIRECTION INPUT ;
    USE SIGNAL ;
    SHAPE ABUTMENT ;
    PORT
      LAYER M4_m ;
      RECT 0 12.672 0.024 12.696 ;
    END
  END rw0_wd_in[231]
  PIN rw0_wd_in[232]
    DIRECTION INPUT ;
    USE SIGNAL ;
    SHAPE ABUTMENT ;
    PORT
      LAYER M4_m ;
      RECT 0 12.72 0.024 12.744 ;
    END
  END rw0_wd_in[232]
  PIN rw0_wd_in[233]
    DIRECTION INPUT ;
    USE SIGNAL ;
    SHAPE ABUTMENT ;
    PORT
      LAYER M4_m ;
      RECT 0 12.768 0.024 12.792 ;
    END
  END rw0_wd_in[233]
  PIN rw0_wd_in[234]
    DIRECTION INPUT ;
    USE SIGNAL ;
    SHAPE ABUTMENT ;
    PORT
      LAYER M4_m ;
      RECT 0 12.816 0.024 12.84 ;
    END
  END rw0_wd_in[234]
  PIN rw0_wd_in[235]
    DIRECTION INPUT ;
    USE SIGNAL ;
    SHAPE ABUTMENT ;
    PORT
      LAYER M4_m ;
      RECT 0 12.864 0.024 12.888 ;
    END
  END rw0_wd_in[235]
  PIN rw0_wd_in[236]
    DIRECTION INPUT ;
    USE SIGNAL ;
    SHAPE ABUTMENT ;
    PORT
      LAYER M4_m ;
      RECT 0 12.912 0.024 12.936 ;
    END
  END rw0_wd_in[236]
  PIN rw0_wd_in[237]
    DIRECTION INPUT ;
    USE SIGNAL ;
    SHAPE ABUTMENT ;
    PORT
      LAYER M4_m ;
      RECT 0 12.96 0.024 12.984 ;
    END
  END rw0_wd_in[237]
  PIN rw0_wd_in[238]
    DIRECTION INPUT ;
    USE SIGNAL ;
    SHAPE ABUTMENT ;
    PORT
      LAYER M4_m ;
      RECT 0 13.008 0.024 13.032 ;
    END
  END rw0_wd_in[238]
  PIN rw0_wd_in[239]
    DIRECTION INPUT ;
    USE SIGNAL ;
    SHAPE ABUTMENT ;
    PORT
      LAYER M4_m ;
      RECT 0 13.056 0.024 13.08 ;
    END
  END rw0_wd_in[239]
  PIN rw0_wd_in[240]
    DIRECTION INPUT ;
    USE SIGNAL ;
    SHAPE ABUTMENT ;
    PORT
      LAYER M4_m ;
      RECT 0 13.104 0.024 13.128 ;
    END
  END rw0_wd_in[240]
  PIN rw0_wd_in[241]
    DIRECTION INPUT ;
    USE SIGNAL ;
    SHAPE ABUTMENT ;
    PORT
      LAYER M4_m ;
      RECT 0 13.152 0.024 13.176 ;
    END
  END rw0_wd_in[241]
  PIN rw0_wd_in[242]
    DIRECTION INPUT ;
    USE SIGNAL ;
    SHAPE ABUTMENT ;
    PORT
      LAYER M4_m ;
      RECT 0 13.2 0.024 13.224 ;
    END
  END rw0_wd_in[242]
  PIN rw0_wd_in[243]
    DIRECTION INPUT ;
    USE SIGNAL ;
    SHAPE ABUTMENT ;
    PORT
      LAYER M4_m ;
      RECT 0 13.248 0.024 13.272 ;
    END
  END rw0_wd_in[243]
  PIN rw0_wd_in[244]
    DIRECTION INPUT ;
    USE SIGNAL ;
    SHAPE ABUTMENT ;
    PORT
      LAYER M4_m ;
      RECT 0 13.296 0.024 13.32 ;
    END
  END rw0_wd_in[244]
  PIN rw0_wd_in[245]
    DIRECTION INPUT ;
    USE SIGNAL ;
    SHAPE ABUTMENT ;
    PORT
      LAYER M4_m ;
      RECT 69.318 0.048 69.342 0.072 ;
    END
  END rw0_wd_in[245]
  PIN rw0_wd_in[246]
    DIRECTION INPUT ;
    USE SIGNAL ;
    SHAPE ABUTMENT ;
    PORT
      LAYER M4_m ;
      RECT 69.318 0.096 69.342 0.12 ;
    END
  END rw0_wd_in[246]
  PIN rw0_wd_in[247]
    DIRECTION INPUT ;
    USE SIGNAL ;
    SHAPE ABUTMENT ;
    PORT
      LAYER M4_m ;
      RECT 69.318 0.144 69.342 0.168 ;
    END
  END rw0_wd_in[247]
  PIN rw0_wd_in[248]
    DIRECTION INPUT ;
    USE SIGNAL ;
    SHAPE ABUTMENT ;
    PORT
      LAYER M4_m ;
      RECT 69.318 0.192 69.342 0.216 ;
    END
  END rw0_wd_in[248]
  PIN rw0_wd_in[249]
    DIRECTION INPUT ;
    USE SIGNAL ;
    SHAPE ABUTMENT ;
    PORT
      LAYER M4_m ;
      RECT 69.318 0.24 69.342 0.264 ;
    END
  END rw0_wd_in[249]
  PIN rw0_wd_in[250]
    DIRECTION INPUT ;
    USE SIGNAL ;
    SHAPE ABUTMENT ;
    PORT
      LAYER M4_m ;
      RECT 69.318 0.288 69.342 0.312 ;
    END
  END rw0_wd_in[250]
  PIN rw0_wd_in[251]
    DIRECTION INPUT ;
    USE SIGNAL ;
    SHAPE ABUTMENT ;
    PORT
      LAYER M4_m ;
      RECT 69.318 0.336 69.342 0.36 ;
    END
  END rw0_wd_in[251]
  PIN rw0_wd_in[252]
    DIRECTION INPUT ;
    USE SIGNAL ;
    SHAPE ABUTMENT ;
    PORT
      LAYER M4_m ;
      RECT 69.318 0.384 69.342 0.408 ;
    END
  END rw0_wd_in[252]
  PIN rw0_wd_in[253]
    DIRECTION INPUT ;
    USE SIGNAL ;
    SHAPE ABUTMENT ;
    PORT
      LAYER M4_m ;
      RECT 69.318 0.432 69.342 0.456 ;
    END
  END rw0_wd_in[253]
  PIN rw0_wd_in[254]
    DIRECTION INPUT ;
    USE SIGNAL ;
    SHAPE ABUTMENT ;
    PORT
      LAYER M4_m ;
      RECT 69.318 0.48 69.342 0.504 ;
    END
  END rw0_wd_in[254]
  PIN rw0_wd_in[255]
    DIRECTION INPUT ;
    USE SIGNAL ;
    SHAPE ABUTMENT ;
    PORT
      LAYER M4_m ;
      RECT 69.318 0.528 69.342 0.552 ;
    END
  END rw0_wd_in[255]
  PIN rw0_rd_out[0]
    DIRECTION OUTPUT ;
    USE SIGNAL ;
    SHAPE ABUTMENT ;
    PORT
      LAYER M4_m ;
      RECT 69.318 0.576 69.342 0.6 ;
    END
  END rw0_rd_out[0]
  PIN rw0_rd_out[1]
    DIRECTION OUTPUT ;
    USE SIGNAL ;
    SHAPE ABUTMENT ;
    PORT
      LAYER M4_m ;
      RECT 69.318 0.624 69.342 0.648 ;
    END
  END rw0_rd_out[1]
  PIN rw0_rd_out[2]
    DIRECTION OUTPUT ;
    USE SIGNAL ;
    SHAPE ABUTMENT ;
    PORT
      LAYER M4_m ;
      RECT 69.318 0.672 69.342 0.696 ;
    END
  END rw0_rd_out[2]
  PIN rw0_rd_out[3]
    DIRECTION OUTPUT ;
    USE SIGNAL ;
    SHAPE ABUTMENT ;
    PORT
      LAYER M4_m ;
      RECT 69.318 0.72 69.342 0.744 ;
    END
  END rw0_rd_out[3]
  PIN rw0_rd_out[4]
    DIRECTION OUTPUT ;
    USE SIGNAL ;
    SHAPE ABUTMENT ;
    PORT
      LAYER M4_m ;
      RECT 69.318 0.768 69.342 0.792 ;
    END
  END rw0_rd_out[4]
  PIN rw0_rd_out[5]
    DIRECTION OUTPUT ;
    USE SIGNAL ;
    SHAPE ABUTMENT ;
    PORT
      LAYER M4_m ;
      RECT 69.318 0.816 69.342 0.84 ;
    END
  END rw0_rd_out[5]
  PIN rw0_rd_out[6]
    DIRECTION OUTPUT ;
    USE SIGNAL ;
    SHAPE ABUTMENT ;
    PORT
      LAYER M4_m ;
      RECT 69.318 0.864 69.342 0.888 ;
    END
  END rw0_rd_out[6]
  PIN rw0_rd_out[7]
    DIRECTION OUTPUT ;
    USE SIGNAL ;
    SHAPE ABUTMENT ;
    PORT
      LAYER M4_m ;
      RECT 69.318 0.912 69.342 0.936 ;
    END
  END rw0_rd_out[7]
  PIN rw0_rd_out[8]
    DIRECTION OUTPUT ;
    USE SIGNAL ;
    SHAPE ABUTMENT ;
    PORT
      LAYER M4_m ;
      RECT 69.318 0.96 69.342 0.984 ;
    END
  END rw0_rd_out[8]
  PIN rw0_rd_out[9]
    DIRECTION OUTPUT ;
    USE SIGNAL ;
    SHAPE ABUTMENT ;
    PORT
      LAYER M4_m ;
      RECT 69.318 1.008 69.342 1.032 ;
    END
  END rw0_rd_out[9]
  PIN rw0_rd_out[10]
    DIRECTION OUTPUT ;
    USE SIGNAL ;
    SHAPE ABUTMENT ;
    PORT
      LAYER M4_m ;
      RECT 69.318 1.056 69.342 1.08 ;
    END
  END rw0_rd_out[10]
  PIN rw0_rd_out[11]
    DIRECTION OUTPUT ;
    USE SIGNAL ;
    SHAPE ABUTMENT ;
    PORT
      LAYER M4_m ;
      RECT 69.318 1.104 69.342 1.128 ;
    END
  END rw0_rd_out[11]
  PIN rw0_rd_out[12]
    DIRECTION OUTPUT ;
    USE SIGNAL ;
    SHAPE ABUTMENT ;
    PORT
      LAYER M4_m ;
      RECT 69.318 1.152 69.342 1.176 ;
    END
  END rw0_rd_out[12]
  PIN rw0_rd_out[13]
    DIRECTION OUTPUT ;
    USE SIGNAL ;
    SHAPE ABUTMENT ;
    PORT
      LAYER M4_m ;
      RECT 69.318 1.2 69.342 1.224 ;
    END
  END rw0_rd_out[13]
  PIN rw0_rd_out[14]
    DIRECTION OUTPUT ;
    USE SIGNAL ;
    SHAPE ABUTMENT ;
    PORT
      LAYER M4_m ;
      RECT 69.318 1.248 69.342 1.272 ;
    END
  END rw0_rd_out[14]
  PIN rw0_rd_out[15]
    DIRECTION OUTPUT ;
    USE SIGNAL ;
    SHAPE ABUTMENT ;
    PORT
      LAYER M4_m ;
      RECT 69.318 1.296 69.342 1.32 ;
    END
  END rw0_rd_out[15]
  PIN rw0_rd_out[16]
    DIRECTION OUTPUT ;
    USE SIGNAL ;
    SHAPE ABUTMENT ;
    PORT
      LAYER M4_m ;
      RECT 69.318 1.344 69.342 1.368 ;
    END
  END rw0_rd_out[16]
  PIN rw0_rd_out[17]
    DIRECTION OUTPUT ;
    USE SIGNAL ;
    SHAPE ABUTMENT ;
    PORT
      LAYER M4_m ;
      RECT 69.318 1.392 69.342 1.416 ;
    END
  END rw0_rd_out[17]
  PIN rw0_rd_out[18]
    DIRECTION OUTPUT ;
    USE SIGNAL ;
    SHAPE ABUTMENT ;
    PORT
      LAYER M4_m ;
      RECT 69.318 1.44 69.342 1.464 ;
    END
  END rw0_rd_out[18]
  PIN rw0_rd_out[19]
    DIRECTION OUTPUT ;
    USE SIGNAL ;
    SHAPE ABUTMENT ;
    PORT
      LAYER M4_m ;
      RECT 69.318 1.488 69.342 1.512 ;
    END
  END rw0_rd_out[19]
  PIN rw0_rd_out[20]
    DIRECTION OUTPUT ;
    USE SIGNAL ;
    SHAPE ABUTMENT ;
    PORT
      LAYER M4_m ;
      RECT 69.318 1.536 69.342 1.56 ;
    END
  END rw0_rd_out[20]
  PIN rw0_rd_out[21]
    DIRECTION OUTPUT ;
    USE SIGNAL ;
    SHAPE ABUTMENT ;
    PORT
      LAYER M4_m ;
      RECT 69.318 1.584 69.342 1.608 ;
    END
  END rw0_rd_out[21]
  PIN rw0_rd_out[22]
    DIRECTION OUTPUT ;
    USE SIGNAL ;
    SHAPE ABUTMENT ;
    PORT
      LAYER M4_m ;
      RECT 69.318 1.632 69.342 1.656 ;
    END
  END rw0_rd_out[22]
  PIN rw0_rd_out[23]
    DIRECTION OUTPUT ;
    USE SIGNAL ;
    SHAPE ABUTMENT ;
    PORT
      LAYER M4_m ;
      RECT 69.318 1.68 69.342 1.704 ;
    END
  END rw0_rd_out[23]
  PIN rw0_rd_out[24]
    DIRECTION OUTPUT ;
    USE SIGNAL ;
    SHAPE ABUTMENT ;
    PORT
      LAYER M4_m ;
      RECT 69.318 1.728 69.342 1.752 ;
    END
  END rw0_rd_out[24]
  PIN rw0_rd_out[25]
    DIRECTION OUTPUT ;
    USE SIGNAL ;
    SHAPE ABUTMENT ;
    PORT
      LAYER M4_m ;
      RECT 69.318 1.776 69.342 1.8 ;
    END
  END rw0_rd_out[25]
  PIN rw0_rd_out[26]
    DIRECTION OUTPUT ;
    USE SIGNAL ;
    SHAPE ABUTMENT ;
    PORT
      LAYER M4_m ;
      RECT 69.318 1.824 69.342 1.848 ;
    END
  END rw0_rd_out[26]
  PIN rw0_rd_out[27]
    DIRECTION OUTPUT ;
    USE SIGNAL ;
    SHAPE ABUTMENT ;
    PORT
      LAYER M4_m ;
      RECT 69.318 1.872 69.342 1.896 ;
    END
  END rw0_rd_out[27]
  PIN rw0_rd_out[28]
    DIRECTION OUTPUT ;
    USE SIGNAL ;
    SHAPE ABUTMENT ;
    PORT
      LAYER M4_m ;
      RECT 69.318 1.92 69.342 1.944 ;
    END
  END rw0_rd_out[28]
  PIN rw0_rd_out[29]
    DIRECTION OUTPUT ;
    USE SIGNAL ;
    SHAPE ABUTMENT ;
    PORT
      LAYER M4_m ;
      RECT 69.318 1.968 69.342 1.992 ;
    END
  END rw0_rd_out[29]
  PIN rw0_rd_out[30]
    DIRECTION OUTPUT ;
    USE SIGNAL ;
    SHAPE ABUTMENT ;
    PORT
      LAYER M4_m ;
      RECT 69.318 2.016 69.342 2.04 ;
    END
  END rw0_rd_out[30]
  PIN rw0_rd_out[31]
    DIRECTION OUTPUT ;
    USE SIGNAL ;
    SHAPE ABUTMENT ;
    PORT
      LAYER M4_m ;
      RECT 69.318 2.064 69.342 2.088 ;
    END
  END rw0_rd_out[31]
  PIN rw0_rd_out[32]
    DIRECTION OUTPUT ;
    USE SIGNAL ;
    SHAPE ABUTMENT ;
    PORT
      LAYER M4_m ;
      RECT 69.318 2.112 69.342 2.136 ;
    END
  END rw0_rd_out[32]
  PIN rw0_rd_out[33]
    DIRECTION OUTPUT ;
    USE SIGNAL ;
    SHAPE ABUTMENT ;
    PORT
      LAYER M4_m ;
      RECT 69.318 2.16 69.342 2.184 ;
    END
  END rw0_rd_out[33]
  PIN rw0_rd_out[34]
    DIRECTION OUTPUT ;
    USE SIGNAL ;
    SHAPE ABUTMENT ;
    PORT
      LAYER M4_m ;
      RECT 69.318 2.208 69.342 2.232 ;
    END
  END rw0_rd_out[34]
  PIN rw0_rd_out[35]
    DIRECTION OUTPUT ;
    USE SIGNAL ;
    SHAPE ABUTMENT ;
    PORT
      LAYER M4_m ;
      RECT 69.318 2.256 69.342 2.28 ;
    END
  END rw0_rd_out[35]
  PIN rw0_rd_out[36]
    DIRECTION OUTPUT ;
    USE SIGNAL ;
    SHAPE ABUTMENT ;
    PORT
      LAYER M4_m ;
      RECT 69.318 2.304 69.342 2.328 ;
    END
  END rw0_rd_out[36]
  PIN rw0_rd_out[37]
    DIRECTION OUTPUT ;
    USE SIGNAL ;
    SHAPE ABUTMENT ;
    PORT
      LAYER M4_m ;
      RECT 69.318 2.352 69.342 2.376 ;
    END
  END rw0_rd_out[37]
  PIN rw0_rd_out[38]
    DIRECTION OUTPUT ;
    USE SIGNAL ;
    SHAPE ABUTMENT ;
    PORT
      LAYER M4_m ;
      RECT 69.318 2.4 69.342 2.424 ;
    END
  END rw0_rd_out[38]
  PIN rw0_rd_out[39]
    DIRECTION OUTPUT ;
    USE SIGNAL ;
    SHAPE ABUTMENT ;
    PORT
      LAYER M4_m ;
      RECT 69.318 2.448 69.342 2.472 ;
    END
  END rw0_rd_out[39]
  PIN rw0_rd_out[40]
    DIRECTION OUTPUT ;
    USE SIGNAL ;
    SHAPE ABUTMENT ;
    PORT
      LAYER M4_m ;
      RECT 69.318 2.496 69.342 2.52 ;
    END
  END rw0_rd_out[40]
  PIN rw0_rd_out[41]
    DIRECTION OUTPUT ;
    USE SIGNAL ;
    SHAPE ABUTMENT ;
    PORT
      LAYER M4_m ;
      RECT 69.318 2.544 69.342 2.568 ;
    END
  END rw0_rd_out[41]
  PIN rw0_rd_out[42]
    DIRECTION OUTPUT ;
    USE SIGNAL ;
    SHAPE ABUTMENT ;
    PORT
      LAYER M4_m ;
      RECT 69.318 2.592 69.342 2.616 ;
    END
  END rw0_rd_out[42]
  PIN rw0_rd_out[43]
    DIRECTION OUTPUT ;
    USE SIGNAL ;
    SHAPE ABUTMENT ;
    PORT
      LAYER M4_m ;
      RECT 69.318 2.64 69.342 2.664 ;
    END
  END rw0_rd_out[43]
  PIN rw0_rd_out[44]
    DIRECTION OUTPUT ;
    USE SIGNAL ;
    SHAPE ABUTMENT ;
    PORT
      LAYER M4_m ;
      RECT 69.318 2.688 69.342 2.712 ;
    END
  END rw0_rd_out[44]
  PIN rw0_rd_out[45]
    DIRECTION OUTPUT ;
    USE SIGNAL ;
    SHAPE ABUTMENT ;
    PORT
      LAYER M4_m ;
      RECT 69.318 2.736 69.342 2.76 ;
    END
  END rw0_rd_out[45]
  PIN rw0_rd_out[46]
    DIRECTION OUTPUT ;
    USE SIGNAL ;
    SHAPE ABUTMENT ;
    PORT
      LAYER M4_m ;
      RECT 69.318 2.784 69.342 2.808 ;
    END
  END rw0_rd_out[46]
  PIN rw0_rd_out[47]
    DIRECTION OUTPUT ;
    USE SIGNAL ;
    SHAPE ABUTMENT ;
    PORT
      LAYER M4_m ;
      RECT 69.318 2.832 69.342 2.856 ;
    END
  END rw0_rd_out[47]
  PIN rw0_rd_out[48]
    DIRECTION OUTPUT ;
    USE SIGNAL ;
    SHAPE ABUTMENT ;
    PORT
      LAYER M4_m ;
      RECT 69.318 2.88 69.342 2.904 ;
    END
  END rw0_rd_out[48]
  PIN rw0_rd_out[49]
    DIRECTION OUTPUT ;
    USE SIGNAL ;
    SHAPE ABUTMENT ;
    PORT
      LAYER M4_m ;
      RECT 69.318 2.928 69.342 2.952 ;
    END
  END rw0_rd_out[49]
  PIN rw0_rd_out[50]
    DIRECTION OUTPUT ;
    USE SIGNAL ;
    SHAPE ABUTMENT ;
    PORT
      LAYER M4_m ;
      RECT 69.318 2.976 69.342 3 ;
    END
  END rw0_rd_out[50]
  PIN rw0_rd_out[51]
    DIRECTION OUTPUT ;
    USE SIGNAL ;
    SHAPE ABUTMENT ;
    PORT
      LAYER M4_m ;
      RECT 69.318 3.024 69.342 3.048 ;
    END
  END rw0_rd_out[51]
  PIN rw0_rd_out[52]
    DIRECTION OUTPUT ;
    USE SIGNAL ;
    SHAPE ABUTMENT ;
    PORT
      LAYER M4_m ;
      RECT 69.318 3.072 69.342 3.096 ;
    END
  END rw0_rd_out[52]
  PIN rw0_rd_out[53]
    DIRECTION OUTPUT ;
    USE SIGNAL ;
    SHAPE ABUTMENT ;
    PORT
      LAYER M4_m ;
      RECT 69.318 3.12 69.342 3.144 ;
    END
  END rw0_rd_out[53]
  PIN rw0_rd_out[54]
    DIRECTION OUTPUT ;
    USE SIGNAL ;
    SHAPE ABUTMENT ;
    PORT
      LAYER M4_m ;
      RECT 69.318 3.168 69.342 3.192 ;
    END
  END rw0_rd_out[54]
  PIN rw0_rd_out[55]
    DIRECTION OUTPUT ;
    USE SIGNAL ;
    SHAPE ABUTMENT ;
    PORT
      LAYER M4_m ;
      RECT 69.318 3.216 69.342 3.24 ;
    END
  END rw0_rd_out[55]
  PIN rw0_rd_out[56]
    DIRECTION OUTPUT ;
    USE SIGNAL ;
    SHAPE ABUTMENT ;
    PORT
      LAYER M4_m ;
      RECT 69.318 3.264 69.342 3.288 ;
    END
  END rw0_rd_out[56]
  PIN rw0_rd_out[57]
    DIRECTION OUTPUT ;
    USE SIGNAL ;
    SHAPE ABUTMENT ;
    PORT
      LAYER M4_m ;
      RECT 69.318 3.312 69.342 3.336 ;
    END
  END rw0_rd_out[57]
  PIN rw0_rd_out[58]
    DIRECTION OUTPUT ;
    USE SIGNAL ;
    SHAPE ABUTMENT ;
    PORT
      LAYER M4_m ;
      RECT 69.318 3.36 69.342 3.384 ;
    END
  END rw0_rd_out[58]
  PIN rw0_rd_out[59]
    DIRECTION OUTPUT ;
    USE SIGNAL ;
    SHAPE ABUTMENT ;
    PORT
      LAYER M4_m ;
      RECT 69.318 3.408 69.342 3.432 ;
    END
  END rw0_rd_out[59]
  PIN rw0_rd_out[60]
    DIRECTION OUTPUT ;
    USE SIGNAL ;
    SHAPE ABUTMENT ;
    PORT
      LAYER M4_m ;
      RECT 69.318 3.456 69.342 3.48 ;
    END
  END rw0_rd_out[60]
  PIN rw0_rd_out[61]
    DIRECTION OUTPUT ;
    USE SIGNAL ;
    SHAPE ABUTMENT ;
    PORT
      LAYER M4_m ;
      RECT 69.318 3.504 69.342 3.528 ;
    END
  END rw0_rd_out[61]
  PIN rw0_rd_out[62]
    DIRECTION OUTPUT ;
    USE SIGNAL ;
    SHAPE ABUTMENT ;
    PORT
      LAYER M4_m ;
      RECT 69.318 3.552 69.342 3.576 ;
    END
  END rw0_rd_out[62]
  PIN rw0_rd_out[63]
    DIRECTION OUTPUT ;
    USE SIGNAL ;
    SHAPE ABUTMENT ;
    PORT
      LAYER M4_m ;
      RECT 69.318 3.6 69.342 3.624 ;
    END
  END rw0_rd_out[63]
  PIN rw0_rd_out[64]
    DIRECTION OUTPUT ;
    USE SIGNAL ;
    SHAPE ABUTMENT ;
    PORT
      LAYER M4_m ;
      RECT 69.318 3.648 69.342 3.672 ;
    END
  END rw0_rd_out[64]
  PIN rw0_rd_out[65]
    DIRECTION OUTPUT ;
    USE SIGNAL ;
    SHAPE ABUTMENT ;
    PORT
      LAYER M4_m ;
      RECT 69.318 3.696 69.342 3.72 ;
    END
  END rw0_rd_out[65]
  PIN rw0_rd_out[66]
    DIRECTION OUTPUT ;
    USE SIGNAL ;
    SHAPE ABUTMENT ;
    PORT
      LAYER M4_m ;
      RECT 69.318 3.744 69.342 3.768 ;
    END
  END rw0_rd_out[66]
  PIN rw0_rd_out[67]
    DIRECTION OUTPUT ;
    USE SIGNAL ;
    SHAPE ABUTMENT ;
    PORT
      LAYER M4_m ;
      RECT 69.318 3.792 69.342 3.816 ;
    END
  END rw0_rd_out[67]
  PIN rw0_rd_out[68]
    DIRECTION OUTPUT ;
    USE SIGNAL ;
    SHAPE ABUTMENT ;
    PORT
      LAYER M4_m ;
      RECT 69.318 3.84 69.342 3.864 ;
    END
  END rw0_rd_out[68]
  PIN rw0_rd_out[69]
    DIRECTION OUTPUT ;
    USE SIGNAL ;
    SHAPE ABUTMENT ;
    PORT
      LAYER M4_m ;
      RECT 69.318 3.888 69.342 3.912 ;
    END
  END rw0_rd_out[69]
  PIN rw0_rd_out[70]
    DIRECTION OUTPUT ;
    USE SIGNAL ;
    SHAPE ABUTMENT ;
    PORT
      LAYER M4_m ;
      RECT 69.318 3.936 69.342 3.96 ;
    END
  END rw0_rd_out[70]
  PIN rw0_rd_out[71]
    DIRECTION OUTPUT ;
    USE SIGNAL ;
    SHAPE ABUTMENT ;
    PORT
      LAYER M4_m ;
      RECT 69.318 3.984 69.342 4.008 ;
    END
  END rw0_rd_out[71]
  PIN rw0_rd_out[72]
    DIRECTION OUTPUT ;
    USE SIGNAL ;
    SHAPE ABUTMENT ;
    PORT
      LAYER M4_m ;
      RECT 69.318 4.032 69.342 4.056 ;
    END
  END rw0_rd_out[72]
  PIN rw0_rd_out[73]
    DIRECTION OUTPUT ;
    USE SIGNAL ;
    SHAPE ABUTMENT ;
    PORT
      LAYER M4_m ;
      RECT 69.318 4.08 69.342 4.104 ;
    END
  END rw0_rd_out[73]
  PIN rw0_rd_out[74]
    DIRECTION OUTPUT ;
    USE SIGNAL ;
    SHAPE ABUTMENT ;
    PORT
      LAYER M4_m ;
      RECT 69.318 4.128 69.342 4.152 ;
    END
  END rw0_rd_out[74]
  PIN rw0_rd_out[75]
    DIRECTION OUTPUT ;
    USE SIGNAL ;
    SHAPE ABUTMENT ;
    PORT
      LAYER M4_m ;
      RECT 69.318 4.176 69.342 4.2 ;
    END
  END rw0_rd_out[75]
  PIN rw0_rd_out[76]
    DIRECTION OUTPUT ;
    USE SIGNAL ;
    SHAPE ABUTMENT ;
    PORT
      LAYER M4_m ;
      RECT 69.318 4.224 69.342 4.248 ;
    END
  END rw0_rd_out[76]
  PIN rw0_rd_out[77]
    DIRECTION OUTPUT ;
    USE SIGNAL ;
    SHAPE ABUTMENT ;
    PORT
      LAYER M4_m ;
      RECT 69.318 4.272 69.342 4.296 ;
    END
  END rw0_rd_out[77]
  PIN rw0_rd_out[78]
    DIRECTION OUTPUT ;
    USE SIGNAL ;
    SHAPE ABUTMENT ;
    PORT
      LAYER M4_m ;
      RECT 69.318 4.32 69.342 4.344 ;
    END
  END rw0_rd_out[78]
  PIN rw0_rd_out[79]
    DIRECTION OUTPUT ;
    USE SIGNAL ;
    SHAPE ABUTMENT ;
    PORT
      LAYER M4_m ;
      RECT 69.318 4.368 69.342 4.392 ;
    END
  END rw0_rd_out[79]
  PIN rw0_rd_out[80]
    DIRECTION OUTPUT ;
    USE SIGNAL ;
    SHAPE ABUTMENT ;
    PORT
      LAYER M4_m ;
      RECT 69.318 4.416 69.342 4.44 ;
    END
  END rw0_rd_out[80]
  PIN rw0_rd_out[81]
    DIRECTION OUTPUT ;
    USE SIGNAL ;
    SHAPE ABUTMENT ;
    PORT
      LAYER M4_m ;
      RECT 69.318 4.464 69.342 4.488 ;
    END
  END rw0_rd_out[81]
  PIN rw0_rd_out[82]
    DIRECTION OUTPUT ;
    USE SIGNAL ;
    SHAPE ABUTMENT ;
    PORT
      LAYER M4_m ;
      RECT 69.318 4.512 69.342 4.536 ;
    END
  END rw0_rd_out[82]
  PIN rw0_rd_out[83]
    DIRECTION OUTPUT ;
    USE SIGNAL ;
    SHAPE ABUTMENT ;
    PORT
      LAYER M4_m ;
      RECT 69.318 4.56 69.342 4.584 ;
    END
  END rw0_rd_out[83]
  PIN rw0_rd_out[84]
    DIRECTION OUTPUT ;
    USE SIGNAL ;
    SHAPE ABUTMENT ;
    PORT
      LAYER M4_m ;
      RECT 69.318 4.608 69.342 4.632 ;
    END
  END rw0_rd_out[84]
  PIN rw0_rd_out[85]
    DIRECTION OUTPUT ;
    USE SIGNAL ;
    SHAPE ABUTMENT ;
    PORT
      LAYER M4_m ;
      RECT 69.318 4.656 69.342 4.68 ;
    END
  END rw0_rd_out[85]
  PIN rw0_rd_out[86]
    DIRECTION OUTPUT ;
    USE SIGNAL ;
    SHAPE ABUTMENT ;
    PORT
      LAYER M4_m ;
      RECT 69.318 4.704 69.342 4.728 ;
    END
  END rw0_rd_out[86]
  PIN rw0_rd_out[87]
    DIRECTION OUTPUT ;
    USE SIGNAL ;
    SHAPE ABUTMENT ;
    PORT
      LAYER M4_m ;
      RECT 69.318 4.752 69.342 4.776 ;
    END
  END rw0_rd_out[87]
  PIN rw0_rd_out[88]
    DIRECTION OUTPUT ;
    USE SIGNAL ;
    SHAPE ABUTMENT ;
    PORT
      LAYER M4_m ;
      RECT 69.318 4.8 69.342 4.824 ;
    END
  END rw0_rd_out[88]
  PIN rw0_rd_out[89]
    DIRECTION OUTPUT ;
    USE SIGNAL ;
    SHAPE ABUTMENT ;
    PORT
      LAYER M4_m ;
      RECT 69.318 4.848 69.342 4.872 ;
    END
  END rw0_rd_out[89]
  PIN rw0_rd_out[90]
    DIRECTION OUTPUT ;
    USE SIGNAL ;
    SHAPE ABUTMENT ;
    PORT
      LAYER M4_m ;
      RECT 69.318 4.896 69.342 4.92 ;
    END
  END rw0_rd_out[90]
  PIN rw0_rd_out[91]
    DIRECTION OUTPUT ;
    USE SIGNAL ;
    SHAPE ABUTMENT ;
    PORT
      LAYER M4_m ;
      RECT 69.318 4.944 69.342 4.968 ;
    END
  END rw0_rd_out[91]
  PIN rw0_rd_out[92]
    DIRECTION OUTPUT ;
    USE SIGNAL ;
    SHAPE ABUTMENT ;
    PORT
      LAYER M4_m ;
      RECT 69.318 4.992 69.342 5.016 ;
    END
  END rw0_rd_out[92]
  PIN rw0_rd_out[93]
    DIRECTION OUTPUT ;
    USE SIGNAL ;
    SHAPE ABUTMENT ;
    PORT
      LAYER M4_m ;
      RECT 69.318 5.04 69.342 5.064 ;
    END
  END rw0_rd_out[93]
  PIN rw0_rd_out[94]
    DIRECTION OUTPUT ;
    USE SIGNAL ;
    SHAPE ABUTMENT ;
    PORT
      LAYER M4_m ;
      RECT 69.318 5.088 69.342 5.112 ;
    END
  END rw0_rd_out[94]
  PIN rw0_rd_out[95]
    DIRECTION OUTPUT ;
    USE SIGNAL ;
    SHAPE ABUTMENT ;
    PORT
      LAYER M4_m ;
      RECT 69.318 5.136 69.342 5.16 ;
    END
  END rw0_rd_out[95]
  PIN rw0_rd_out[96]
    DIRECTION OUTPUT ;
    USE SIGNAL ;
    SHAPE ABUTMENT ;
    PORT
      LAYER M4_m ;
      RECT 69.318 5.184 69.342 5.208 ;
    END
  END rw0_rd_out[96]
  PIN rw0_rd_out[97]
    DIRECTION OUTPUT ;
    USE SIGNAL ;
    SHAPE ABUTMENT ;
    PORT
      LAYER M4_m ;
      RECT 69.318 5.232 69.342 5.256 ;
    END
  END rw0_rd_out[97]
  PIN rw0_rd_out[98]
    DIRECTION OUTPUT ;
    USE SIGNAL ;
    SHAPE ABUTMENT ;
    PORT
      LAYER M4_m ;
      RECT 69.318 5.28 69.342 5.304 ;
    END
  END rw0_rd_out[98]
  PIN rw0_rd_out[99]
    DIRECTION OUTPUT ;
    USE SIGNAL ;
    SHAPE ABUTMENT ;
    PORT
      LAYER M4_m ;
      RECT 69.318 5.328 69.342 5.352 ;
    END
  END rw0_rd_out[99]
  PIN rw0_rd_out[100]
    DIRECTION OUTPUT ;
    USE SIGNAL ;
    SHAPE ABUTMENT ;
    PORT
      LAYER M4_m ;
      RECT 69.318 5.376 69.342 5.4 ;
    END
  END rw0_rd_out[100]
  PIN rw0_rd_out[101]
    DIRECTION OUTPUT ;
    USE SIGNAL ;
    SHAPE ABUTMENT ;
    PORT
      LAYER M4_m ;
      RECT 69.318 5.424 69.342 5.448 ;
    END
  END rw0_rd_out[101]
  PIN rw0_rd_out[102]
    DIRECTION OUTPUT ;
    USE SIGNAL ;
    SHAPE ABUTMENT ;
    PORT
      LAYER M4_m ;
      RECT 69.318 5.472 69.342 5.496 ;
    END
  END rw0_rd_out[102]
  PIN rw0_rd_out[103]
    DIRECTION OUTPUT ;
    USE SIGNAL ;
    SHAPE ABUTMENT ;
    PORT
      LAYER M4_m ;
      RECT 69.318 5.52 69.342 5.544 ;
    END
  END rw0_rd_out[103]
  PIN rw0_rd_out[104]
    DIRECTION OUTPUT ;
    USE SIGNAL ;
    SHAPE ABUTMENT ;
    PORT
      LAYER M4_m ;
      RECT 69.318 5.568 69.342 5.592 ;
    END
  END rw0_rd_out[104]
  PIN rw0_rd_out[105]
    DIRECTION OUTPUT ;
    USE SIGNAL ;
    SHAPE ABUTMENT ;
    PORT
      LAYER M4_m ;
      RECT 69.318 5.616 69.342 5.64 ;
    END
  END rw0_rd_out[105]
  PIN rw0_rd_out[106]
    DIRECTION OUTPUT ;
    USE SIGNAL ;
    SHAPE ABUTMENT ;
    PORT
      LAYER M4_m ;
      RECT 69.318 5.664 69.342 5.688 ;
    END
  END rw0_rd_out[106]
  PIN rw0_rd_out[107]
    DIRECTION OUTPUT ;
    USE SIGNAL ;
    SHAPE ABUTMENT ;
    PORT
      LAYER M4_m ;
      RECT 69.318 5.712 69.342 5.736 ;
    END
  END rw0_rd_out[107]
  PIN rw0_rd_out[108]
    DIRECTION OUTPUT ;
    USE SIGNAL ;
    SHAPE ABUTMENT ;
    PORT
      LAYER M4_m ;
      RECT 69.318 5.76 69.342 5.784 ;
    END
  END rw0_rd_out[108]
  PIN rw0_rd_out[109]
    DIRECTION OUTPUT ;
    USE SIGNAL ;
    SHAPE ABUTMENT ;
    PORT
      LAYER M4_m ;
      RECT 69.318 5.808 69.342 5.832 ;
    END
  END rw0_rd_out[109]
  PIN rw0_rd_out[110]
    DIRECTION OUTPUT ;
    USE SIGNAL ;
    SHAPE ABUTMENT ;
    PORT
      LAYER M4_m ;
      RECT 69.318 5.856 69.342 5.88 ;
    END
  END rw0_rd_out[110]
  PIN rw0_rd_out[111]
    DIRECTION OUTPUT ;
    USE SIGNAL ;
    SHAPE ABUTMENT ;
    PORT
      LAYER M4_m ;
      RECT 69.318 5.904 69.342 5.928 ;
    END
  END rw0_rd_out[111]
  PIN rw0_rd_out[112]
    DIRECTION OUTPUT ;
    USE SIGNAL ;
    SHAPE ABUTMENT ;
    PORT
      LAYER M4_m ;
      RECT 69.318 5.952 69.342 5.976 ;
    END
  END rw0_rd_out[112]
  PIN rw0_rd_out[113]
    DIRECTION OUTPUT ;
    USE SIGNAL ;
    SHAPE ABUTMENT ;
    PORT
      LAYER M4_m ;
      RECT 69.318 6 69.342 6.024 ;
    END
  END rw0_rd_out[113]
  PIN rw0_rd_out[114]
    DIRECTION OUTPUT ;
    USE SIGNAL ;
    SHAPE ABUTMENT ;
    PORT
      LAYER M4_m ;
      RECT 69.318 6.048 69.342 6.072 ;
    END
  END rw0_rd_out[114]
  PIN rw0_rd_out[115]
    DIRECTION OUTPUT ;
    USE SIGNAL ;
    SHAPE ABUTMENT ;
    PORT
      LAYER M4_m ;
      RECT 69.318 6.096 69.342 6.12 ;
    END
  END rw0_rd_out[115]
  PIN rw0_rd_out[116]
    DIRECTION OUTPUT ;
    USE SIGNAL ;
    SHAPE ABUTMENT ;
    PORT
      LAYER M4_m ;
      RECT 69.318 6.144 69.342 6.168 ;
    END
  END rw0_rd_out[116]
  PIN rw0_rd_out[117]
    DIRECTION OUTPUT ;
    USE SIGNAL ;
    SHAPE ABUTMENT ;
    PORT
      LAYER M4_m ;
      RECT 69.318 6.192 69.342 6.216 ;
    END
  END rw0_rd_out[117]
  PIN rw0_rd_out[118]
    DIRECTION OUTPUT ;
    USE SIGNAL ;
    SHAPE ABUTMENT ;
    PORT
      LAYER M4_m ;
      RECT 69.318 6.24 69.342 6.264 ;
    END
  END rw0_rd_out[118]
  PIN rw0_rd_out[119]
    DIRECTION OUTPUT ;
    USE SIGNAL ;
    SHAPE ABUTMENT ;
    PORT
      LAYER M4_m ;
      RECT 69.318 6.288 69.342 6.312 ;
    END
  END rw0_rd_out[119]
  PIN rw0_rd_out[120]
    DIRECTION OUTPUT ;
    USE SIGNAL ;
    SHAPE ABUTMENT ;
    PORT
      LAYER M4_m ;
      RECT 69.318 6.336 69.342 6.36 ;
    END
  END rw0_rd_out[120]
  PIN rw0_rd_out[121]
    DIRECTION OUTPUT ;
    USE SIGNAL ;
    SHAPE ABUTMENT ;
    PORT
      LAYER M4_m ;
      RECT 69.318 6.384 69.342 6.408 ;
    END
  END rw0_rd_out[121]
  PIN rw0_rd_out[122]
    DIRECTION OUTPUT ;
    USE SIGNAL ;
    SHAPE ABUTMENT ;
    PORT
      LAYER M4_m ;
      RECT 69.318 6.432 69.342 6.456 ;
    END
  END rw0_rd_out[122]
  PIN rw0_rd_out[123]
    DIRECTION OUTPUT ;
    USE SIGNAL ;
    SHAPE ABUTMENT ;
    PORT
      LAYER M4_m ;
      RECT 69.318 6.48 69.342 6.504 ;
    END
  END rw0_rd_out[123]
  PIN rw0_rd_out[124]
    DIRECTION OUTPUT ;
    USE SIGNAL ;
    SHAPE ABUTMENT ;
    PORT
      LAYER M4_m ;
      RECT 69.318 6.528 69.342 6.552 ;
    END
  END rw0_rd_out[124]
  PIN rw0_rd_out[125]
    DIRECTION OUTPUT ;
    USE SIGNAL ;
    SHAPE ABUTMENT ;
    PORT
      LAYER M4_m ;
      RECT 69.318 6.576 69.342 6.6 ;
    END
  END rw0_rd_out[125]
  PIN rw0_rd_out[126]
    DIRECTION OUTPUT ;
    USE SIGNAL ;
    SHAPE ABUTMENT ;
    PORT
      LAYER M4_m ;
      RECT 69.318 6.624 69.342 6.648 ;
    END
  END rw0_rd_out[126]
  PIN rw0_rd_out[127]
    DIRECTION OUTPUT ;
    USE SIGNAL ;
    SHAPE ABUTMENT ;
    PORT
      LAYER M4_m ;
      RECT 69.318 6.672 69.342 6.696 ;
    END
  END rw0_rd_out[127]
  PIN rw0_rd_out[128]
    DIRECTION OUTPUT ;
    USE SIGNAL ;
    SHAPE ABUTMENT ;
    PORT
      LAYER M4_m ;
      RECT 69.318 6.72 69.342 6.744 ;
    END
  END rw0_rd_out[128]
  PIN rw0_rd_out[129]
    DIRECTION OUTPUT ;
    USE SIGNAL ;
    SHAPE ABUTMENT ;
    PORT
      LAYER M4_m ;
      RECT 69.318 6.768 69.342 6.792 ;
    END
  END rw0_rd_out[129]
  PIN rw0_rd_out[130]
    DIRECTION OUTPUT ;
    USE SIGNAL ;
    SHAPE ABUTMENT ;
    PORT
      LAYER M4_m ;
      RECT 69.318 6.816 69.342 6.84 ;
    END
  END rw0_rd_out[130]
  PIN rw0_rd_out[131]
    DIRECTION OUTPUT ;
    USE SIGNAL ;
    SHAPE ABUTMENT ;
    PORT
      LAYER M4_m ;
      RECT 69.318 6.864 69.342 6.888 ;
    END
  END rw0_rd_out[131]
  PIN rw0_rd_out[132]
    DIRECTION OUTPUT ;
    USE SIGNAL ;
    SHAPE ABUTMENT ;
    PORT
      LAYER M4_m ;
      RECT 69.318 6.912 69.342 6.936 ;
    END
  END rw0_rd_out[132]
  PIN rw0_rd_out[133]
    DIRECTION OUTPUT ;
    USE SIGNAL ;
    SHAPE ABUTMENT ;
    PORT
      LAYER M4_m ;
      RECT 69.318 6.96 69.342 6.984 ;
    END
  END rw0_rd_out[133]
  PIN rw0_rd_out[134]
    DIRECTION OUTPUT ;
    USE SIGNAL ;
    SHAPE ABUTMENT ;
    PORT
      LAYER M4_m ;
      RECT 69.318 7.008 69.342 7.032 ;
    END
  END rw0_rd_out[134]
  PIN rw0_rd_out[135]
    DIRECTION OUTPUT ;
    USE SIGNAL ;
    SHAPE ABUTMENT ;
    PORT
      LAYER M4_m ;
      RECT 69.318 7.056 69.342 7.08 ;
    END
  END rw0_rd_out[135]
  PIN rw0_rd_out[136]
    DIRECTION OUTPUT ;
    USE SIGNAL ;
    SHAPE ABUTMENT ;
    PORT
      LAYER M4_m ;
      RECT 69.318 7.104 69.342 7.128 ;
    END
  END rw0_rd_out[136]
  PIN rw0_rd_out[137]
    DIRECTION OUTPUT ;
    USE SIGNAL ;
    SHAPE ABUTMENT ;
    PORT
      LAYER M4_m ;
      RECT 69.318 7.152 69.342 7.176 ;
    END
  END rw0_rd_out[137]
  PIN rw0_rd_out[138]
    DIRECTION OUTPUT ;
    USE SIGNAL ;
    SHAPE ABUTMENT ;
    PORT
      LAYER M4_m ;
      RECT 69.318 7.2 69.342 7.224 ;
    END
  END rw0_rd_out[138]
  PIN rw0_rd_out[139]
    DIRECTION OUTPUT ;
    USE SIGNAL ;
    SHAPE ABUTMENT ;
    PORT
      LAYER M4_m ;
      RECT 69.318 7.248 69.342 7.272 ;
    END
  END rw0_rd_out[139]
  PIN rw0_rd_out[140]
    DIRECTION OUTPUT ;
    USE SIGNAL ;
    SHAPE ABUTMENT ;
    PORT
      LAYER M4_m ;
      RECT 69.318 7.296 69.342 7.32 ;
    END
  END rw0_rd_out[140]
  PIN rw0_rd_out[141]
    DIRECTION OUTPUT ;
    USE SIGNAL ;
    SHAPE ABUTMENT ;
    PORT
      LAYER M4_m ;
      RECT 69.318 7.344 69.342 7.368 ;
    END
  END rw0_rd_out[141]
  PIN rw0_rd_out[142]
    DIRECTION OUTPUT ;
    USE SIGNAL ;
    SHAPE ABUTMENT ;
    PORT
      LAYER M4_m ;
      RECT 69.318 7.392 69.342 7.416 ;
    END
  END rw0_rd_out[142]
  PIN rw0_rd_out[143]
    DIRECTION OUTPUT ;
    USE SIGNAL ;
    SHAPE ABUTMENT ;
    PORT
      LAYER M4_m ;
      RECT 69.318 7.44 69.342 7.464 ;
    END
  END rw0_rd_out[143]
  PIN rw0_rd_out[144]
    DIRECTION OUTPUT ;
    USE SIGNAL ;
    SHAPE ABUTMENT ;
    PORT
      LAYER M4_m ;
      RECT 69.318 7.488 69.342 7.512 ;
    END
  END rw0_rd_out[144]
  PIN rw0_rd_out[145]
    DIRECTION OUTPUT ;
    USE SIGNAL ;
    SHAPE ABUTMENT ;
    PORT
      LAYER M4_m ;
      RECT 69.318 7.536 69.342 7.56 ;
    END
  END rw0_rd_out[145]
  PIN rw0_rd_out[146]
    DIRECTION OUTPUT ;
    USE SIGNAL ;
    SHAPE ABUTMENT ;
    PORT
      LAYER M4_m ;
      RECT 69.318 7.584 69.342 7.608 ;
    END
  END rw0_rd_out[146]
  PIN rw0_rd_out[147]
    DIRECTION OUTPUT ;
    USE SIGNAL ;
    SHAPE ABUTMENT ;
    PORT
      LAYER M4_m ;
      RECT 69.318 7.632 69.342 7.656 ;
    END
  END rw0_rd_out[147]
  PIN rw0_rd_out[148]
    DIRECTION OUTPUT ;
    USE SIGNAL ;
    SHAPE ABUTMENT ;
    PORT
      LAYER M4_m ;
      RECT 69.318 7.68 69.342 7.704 ;
    END
  END rw0_rd_out[148]
  PIN rw0_rd_out[149]
    DIRECTION OUTPUT ;
    USE SIGNAL ;
    SHAPE ABUTMENT ;
    PORT
      LAYER M4_m ;
      RECT 69.318 7.728 69.342 7.752 ;
    END
  END rw0_rd_out[149]
  PIN rw0_rd_out[150]
    DIRECTION OUTPUT ;
    USE SIGNAL ;
    SHAPE ABUTMENT ;
    PORT
      LAYER M4_m ;
      RECT 69.318 7.776 69.342 7.8 ;
    END
  END rw0_rd_out[150]
  PIN rw0_rd_out[151]
    DIRECTION OUTPUT ;
    USE SIGNAL ;
    SHAPE ABUTMENT ;
    PORT
      LAYER M4_m ;
      RECT 69.318 7.824 69.342 7.848 ;
    END
  END rw0_rd_out[151]
  PIN rw0_rd_out[152]
    DIRECTION OUTPUT ;
    USE SIGNAL ;
    SHAPE ABUTMENT ;
    PORT
      LAYER M4_m ;
      RECT 69.318 7.872 69.342 7.896 ;
    END
  END rw0_rd_out[152]
  PIN rw0_rd_out[153]
    DIRECTION OUTPUT ;
    USE SIGNAL ;
    SHAPE ABUTMENT ;
    PORT
      LAYER M4_m ;
      RECT 69.318 7.92 69.342 7.944 ;
    END
  END rw0_rd_out[153]
  PIN rw0_rd_out[154]
    DIRECTION OUTPUT ;
    USE SIGNAL ;
    SHAPE ABUTMENT ;
    PORT
      LAYER M4_m ;
      RECT 69.318 7.968 69.342 7.992 ;
    END
  END rw0_rd_out[154]
  PIN rw0_rd_out[155]
    DIRECTION OUTPUT ;
    USE SIGNAL ;
    SHAPE ABUTMENT ;
    PORT
      LAYER M4_m ;
      RECT 69.318 8.016 69.342 8.04 ;
    END
  END rw0_rd_out[155]
  PIN rw0_rd_out[156]
    DIRECTION OUTPUT ;
    USE SIGNAL ;
    SHAPE ABUTMENT ;
    PORT
      LAYER M4_m ;
      RECT 69.318 8.064 69.342 8.088 ;
    END
  END rw0_rd_out[156]
  PIN rw0_rd_out[157]
    DIRECTION OUTPUT ;
    USE SIGNAL ;
    SHAPE ABUTMENT ;
    PORT
      LAYER M4_m ;
      RECT 69.318 8.112 69.342 8.136 ;
    END
  END rw0_rd_out[157]
  PIN rw0_rd_out[158]
    DIRECTION OUTPUT ;
    USE SIGNAL ;
    SHAPE ABUTMENT ;
    PORT
      LAYER M4_m ;
      RECT 69.318 8.16 69.342 8.184 ;
    END
  END rw0_rd_out[158]
  PIN rw0_rd_out[159]
    DIRECTION OUTPUT ;
    USE SIGNAL ;
    SHAPE ABUTMENT ;
    PORT
      LAYER M4_m ;
      RECT 69.318 8.208 69.342 8.232 ;
    END
  END rw0_rd_out[159]
  PIN rw0_rd_out[160]
    DIRECTION OUTPUT ;
    USE SIGNAL ;
    SHAPE ABUTMENT ;
    PORT
      LAYER M4_m ;
      RECT 69.318 8.256 69.342 8.28 ;
    END
  END rw0_rd_out[160]
  PIN rw0_rd_out[161]
    DIRECTION OUTPUT ;
    USE SIGNAL ;
    SHAPE ABUTMENT ;
    PORT
      LAYER M4_m ;
      RECT 69.318 8.304 69.342 8.328 ;
    END
  END rw0_rd_out[161]
  PIN rw0_rd_out[162]
    DIRECTION OUTPUT ;
    USE SIGNAL ;
    SHAPE ABUTMENT ;
    PORT
      LAYER M4_m ;
      RECT 69.318 8.352 69.342 8.376 ;
    END
  END rw0_rd_out[162]
  PIN rw0_rd_out[163]
    DIRECTION OUTPUT ;
    USE SIGNAL ;
    SHAPE ABUTMENT ;
    PORT
      LAYER M4_m ;
      RECT 69.318 8.4 69.342 8.424 ;
    END
  END rw0_rd_out[163]
  PIN rw0_rd_out[164]
    DIRECTION OUTPUT ;
    USE SIGNAL ;
    SHAPE ABUTMENT ;
    PORT
      LAYER M4_m ;
      RECT 69.318 8.448 69.342 8.472 ;
    END
  END rw0_rd_out[164]
  PIN rw0_rd_out[165]
    DIRECTION OUTPUT ;
    USE SIGNAL ;
    SHAPE ABUTMENT ;
    PORT
      LAYER M4_m ;
      RECT 69.318 8.496 69.342 8.52 ;
    END
  END rw0_rd_out[165]
  PIN rw0_rd_out[166]
    DIRECTION OUTPUT ;
    USE SIGNAL ;
    SHAPE ABUTMENT ;
    PORT
      LAYER M4_m ;
      RECT 69.318 8.544 69.342 8.568 ;
    END
  END rw0_rd_out[166]
  PIN rw0_rd_out[167]
    DIRECTION OUTPUT ;
    USE SIGNAL ;
    SHAPE ABUTMENT ;
    PORT
      LAYER M4_m ;
      RECT 69.318 8.592 69.342 8.616 ;
    END
  END rw0_rd_out[167]
  PIN rw0_rd_out[168]
    DIRECTION OUTPUT ;
    USE SIGNAL ;
    SHAPE ABUTMENT ;
    PORT
      LAYER M4_m ;
      RECT 69.318 8.64 69.342 8.664 ;
    END
  END rw0_rd_out[168]
  PIN rw0_rd_out[169]
    DIRECTION OUTPUT ;
    USE SIGNAL ;
    SHAPE ABUTMENT ;
    PORT
      LAYER M4_m ;
      RECT 69.318 8.688 69.342 8.712 ;
    END
  END rw0_rd_out[169]
  PIN rw0_rd_out[170]
    DIRECTION OUTPUT ;
    USE SIGNAL ;
    SHAPE ABUTMENT ;
    PORT
      LAYER M4_m ;
      RECT 69.318 8.736 69.342 8.76 ;
    END
  END rw0_rd_out[170]
  PIN rw0_rd_out[171]
    DIRECTION OUTPUT ;
    USE SIGNAL ;
    SHAPE ABUTMENT ;
    PORT
      LAYER M4_m ;
      RECT 69.318 8.784 69.342 8.808 ;
    END
  END rw0_rd_out[171]
  PIN rw0_rd_out[172]
    DIRECTION OUTPUT ;
    USE SIGNAL ;
    SHAPE ABUTMENT ;
    PORT
      LAYER M4_m ;
      RECT 69.318 8.832 69.342 8.856 ;
    END
  END rw0_rd_out[172]
  PIN rw0_rd_out[173]
    DIRECTION OUTPUT ;
    USE SIGNAL ;
    SHAPE ABUTMENT ;
    PORT
      LAYER M4_m ;
      RECT 69.318 8.88 69.342 8.904 ;
    END
  END rw0_rd_out[173]
  PIN rw0_rd_out[174]
    DIRECTION OUTPUT ;
    USE SIGNAL ;
    SHAPE ABUTMENT ;
    PORT
      LAYER M4_m ;
      RECT 69.318 8.928 69.342 8.952 ;
    END
  END rw0_rd_out[174]
  PIN rw0_rd_out[175]
    DIRECTION OUTPUT ;
    USE SIGNAL ;
    SHAPE ABUTMENT ;
    PORT
      LAYER M4_m ;
      RECT 69.318 8.976 69.342 9 ;
    END
  END rw0_rd_out[175]
  PIN rw0_rd_out[176]
    DIRECTION OUTPUT ;
    USE SIGNAL ;
    SHAPE ABUTMENT ;
    PORT
      LAYER M4_m ;
      RECT 69.318 9.024 69.342 9.048 ;
    END
  END rw0_rd_out[176]
  PIN rw0_rd_out[177]
    DIRECTION OUTPUT ;
    USE SIGNAL ;
    SHAPE ABUTMENT ;
    PORT
      LAYER M4_m ;
      RECT 69.318 9.072 69.342 9.096 ;
    END
  END rw0_rd_out[177]
  PIN rw0_rd_out[178]
    DIRECTION OUTPUT ;
    USE SIGNAL ;
    SHAPE ABUTMENT ;
    PORT
      LAYER M4_m ;
      RECT 69.318 9.12 69.342 9.144 ;
    END
  END rw0_rd_out[178]
  PIN rw0_rd_out[179]
    DIRECTION OUTPUT ;
    USE SIGNAL ;
    SHAPE ABUTMENT ;
    PORT
      LAYER M4_m ;
      RECT 69.318 9.168 69.342 9.192 ;
    END
  END rw0_rd_out[179]
  PIN rw0_rd_out[180]
    DIRECTION OUTPUT ;
    USE SIGNAL ;
    SHAPE ABUTMENT ;
    PORT
      LAYER M4_m ;
      RECT 69.318 9.216 69.342 9.24 ;
    END
  END rw0_rd_out[180]
  PIN rw0_rd_out[181]
    DIRECTION OUTPUT ;
    USE SIGNAL ;
    SHAPE ABUTMENT ;
    PORT
      LAYER M4_m ;
      RECT 69.318 9.264 69.342 9.288 ;
    END
  END rw0_rd_out[181]
  PIN rw0_rd_out[182]
    DIRECTION OUTPUT ;
    USE SIGNAL ;
    SHAPE ABUTMENT ;
    PORT
      LAYER M4_m ;
      RECT 69.318 9.312 69.342 9.336 ;
    END
  END rw0_rd_out[182]
  PIN rw0_rd_out[183]
    DIRECTION OUTPUT ;
    USE SIGNAL ;
    SHAPE ABUTMENT ;
    PORT
      LAYER M4_m ;
      RECT 69.318 9.36 69.342 9.384 ;
    END
  END rw0_rd_out[183]
  PIN rw0_rd_out[184]
    DIRECTION OUTPUT ;
    USE SIGNAL ;
    SHAPE ABUTMENT ;
    PORT
      LAYER M4_m ;
      RECT 69.318 9.408 69.342 9.432 ;
    END
  END rw0_rd_out[184]
  PIN rw0_rd_out[185]
    DIRECTION OUTPUT ;
    USE SIGNAL ;
    SHAPE ABUTMENT ;
    PORT
      LAYER M4_m ;
      RECT 69.318 9.456 69.342 9.48 ;
    END
  END rw0_rd_out[185]
  PIN rw0_rd_out[186]
    DIRECTION OUTPUT ;
    USE SIGNAL ;
    SHAPE ABUTMENT ;
    PORT
      LAYER M4_m ;
      RECT 69.318 9.504 69.342 9.528 ;
    END
  END rw0_rd_out[186]
  PIN rw0_rd_out[187]
    DIRECTION OUTPUT ;
    USE SIGNAL ;
    SHAPE ABUTMENT ;
    PORT
      LAYER M4_m ;
      RECT 69.318 9.552 69.342 9.576 ;
    END
  END rw0_rd_out[187]
  PIN rw0_rd_out[188]
    DIRECTION OUTPUT ;
    USE SIGNAL ;
    SHAPE ABUTMENT ;
    PORT
      LAYER M4_m ;
      RECT 69.318 9.6 69.342 9.624 ;
    END
  END rw0_rd_out[188]
  PIN rw0_rd_out[189]
    DIRECTION OUTPUT ;
    USE SIGNAL ;
    SHAPE ABUTMENT ;
    PORT
      LAYER M4_m ;
      RECT 69.318 9.648 69.342 9.672 ;
    END
  END rw0_rd_out[189]
  PIN rw0_rd_out[190]
    DIRECTION OUTPUT ;
    USE SIGNAL ;
    SHAPE ABUTMENT ;
    PORT
      LAYER M4_m ;
      RECT 69.318 9.696 69.342 9.72 ;
    END
  END rw0_rd_out[190]
  PIN rw0_rd_out[191]
    DIRECTION OUTPUT ;
    USE SIGNAL ;
    SHAPE ABUTMENT ;
    PORT
      LAYER M4_m ;
      RECT 69.318 9.744 69.342 9.768 ;
    END
  END rw0_rd_out[191]
  PIN rw0_rd_out[192]
    DIRECTION OUTPUT ;
    USE SIGNAL ;
    SHAPE ABUTMENT ;
    PORT
      LAYER M4_m ;
      RECT 69.318 9.792 69.342 9.816 ;
    END
  END rw0_rd_out[192]
  PIN rw0_rd_out[193]
    DIRECTION OUTPUT ;
    USE SIGNAL ;
    SHAPE ABUTMENT ;
    PORT
      LAYER M4_m ;
      RECT 69.318 9.84 69.342 9.864 ;
    END
  END rw0_rd_out[193]
  PIN rw0_rd_out[194]
    DIRECTION OUTPUT ;
    USE SIGNAL ;
    SHAPE ABUTMENT ;
    PORT
      LAYER M4_m ;
      RECT 69.318 9.888 69.342 9.912 ;
    END
  END rw0_rd_out[194]
  PIN rw0_rd_out[195]
    DIRECTION OUTPUT ;
    USE SIGNAL ;
    SHAPE ABUTMENT ;
    PORT
      LAYER M4_m ;
      RECT 69.318 9.936 69.342 9.96 ;
    END
  END rw0_rd_out[195]
  PIN rw0_rd_out[196]
    DIRECTION OUTPUT ;
    USE SIGNAL ;
    SHAPE ABUTMENT ;
    PORT
      LAYER M4_m ;
      RECT 69.318 9.984 69.342 10.008 ;
    END
  END rw0_rd_out[196]
  PIN rw0_rd_out[197]
    DIRECTION OUTPUT ;
    USE SIGNAL ;
    SHAPE ABUTMENT ;
    PORT
      LAYER M4_m ;
      RECT 69.318 10.032 69.342 10.056 ;
    END
  END rw0_rd_out[197]
  PIN rw0_rd_out[198]
    DIRECTION OUTPUT ;
    USE SIGNAL ;
    SHAPE ABUTMENT ;
    PORT
      LAYER M4_m ;
      RECT 69.318 10.08 69.342 10.104 ;
    END
  END rw0_rd_out[198]
  PIN rw0_rd_out[199]
    DIRECTION OUTPUT ;
    USE SIGNAL ;
    SHAPE ABUTMENT ;
    PORT
      LAYER M4_m ;
      RECT 69.318 10.128 69.342 10.152 ;
    END
  END rw0_rd_out[199]
  PIN rw0_rd_out[200]
    DIRECTION OUTPUT ;
    USE SIGNAL ;
    SHAPE ABUTMENT ;
    PORT
      LAYER M4_m ;
      RECT 69.318 10.176 69.342 10.2 ;
    END
  END rw0_rd_out[200]
  PIN rw0_rd_out[201]
    DIRECTION OUTPUT ;
    USE SIGNAL ;
    SHAPE ABUTMENT ;
    PORT
      LAYER M4_m ;
      RECT 69.318 10.224 69.342 10.248 ;
    END
  END rw0_rd_out[201]
  PIN rw0_rd_out[202]
    DIRECTION OUTPUT ;
    USE SIGNAL ;
    SHAPE ABUTMENT ;
    PORT
      LAYER M4_m ;
      RECT 69.318 10.272 69.342 10.296 ;
    END
  END rw0_rd_out[202]
  PIN rw0_rd_out[203]
    DIRECTION OUTPUT ;
    USE SIGNAL ;
    SHAPE ABUTMENT ;
    PORT
      LAYER M4_m ;
      RECT 69.318 10.32 69.342 10.344 ;
    END
  END rw0_rd_out[203]
  PIN rw0_rd_out[204]
    DIRECTION OUTPUT ;
    USE SIGNAL ;
    SHAPE ABUTMENT ;
    PORT
      LAYER M4_m ;
      RECT 69.318 10.368 69.342 10.392 ;
    END
  END rw0_rd_out[204]
  PIN rw0_rd_out[205]
    DIRECTION OUTPUT ;
    USE SIGNAL ;
    SHAPE ABUTMENT ;
    PORT
      LAYER M4_m ;
      RECT 69.318 10.416 69.342 10.44 ;
    END
  END rw0_rd_out[205]
  PIN rw0_rd_out[206]
    DIRECTION OUTPUT ;
    USE SIGNAL ;
    SHAPE ABUTMENT ;
    PORT
      LAYER M4_m ;
      RECT 69.318 10.464 69.342 10.488 ;
    END
  END rw0_rd_out[206]
  PIN rw0_rd_out[207]
    DIRECTION OUTPUT ;
    USE SIGNAL ;
    SHAPE ABUTMENT ;
    PORT
      LAYER M4_m ;
      RECT 69.318 10.512 69.342 10.536 ;
    END
  END rw0_rd_out[207]
  PIN rw0_rd_out[208]
    DIRECTION OUTPUT ;
    USE SIGNAL ;
    SHAPE ABUTMENT ;
    PORT
      LAYER M4_m ;
      RECT 69.318 10.56 69.342 10.584 ;
    END
  END rw0_rd_out[208]
  PIN rw0_rd_out[209]
    DIRECTION OUTPUT ;
    USE SIGNAL ;
    SHAPE ABUTMENT ;
    PORT
      LAYER M4_m ;
      RECT 69.318 10.608 69.342 10.632 ;
    END
  END rw0_rd_out[209]
  PIN rw0_rd_out[210]
    DIRECTION OUTPUT ;
    USE SIGNAL ;
    SHAPE ABUTMENT ;
    PORT
      LAYER M4_m ;
      RECT 69.318 10.656 69.342 10.68 ;
    END
  END rw0_rd_out[210]
  PIN rw0_rd_out[211]
    DIRECTION OUTPUT ;
    USE SIGNAL ;
    SHAPE ABUTMENT ;
    PORT
      LAYER M4_m ;
      RECT 69.318 10.704 69.342 10.728 ;
    END
  END rw0_rd_out[211]
  PIN rw0_rd_out[212]
    DIRECTION OUTPUT ;
    USE SIGNAL ;
    SHAPE ABUTMENT ;
    PORT
      LAYER M4_m ;
      RECT 69.318 10.752 69.342 10.776 ;
    END
  END rw0_rd_out[212]
  PIN rw0_rd_out[213]
    DIRECTION OUTPUT ;
    USE SIGNAL ;
    SHAPE ABUTMENT ;
    PORT
      LAYER M4_m ;
      RECT 69.318 10.8 69.342 10.824 ;
    END
  END rw0_rd_out[213]
  PIN rw0_rd_out[214]
    DIRECTION OUTPUT ;
    USE SIGNAL ;
    SHAPE ABUTMENT ;
    PORT
      LAYER M4_m ;
      RECT 69.318 10.848 69.342 10.872 ;
    END
  END rw0_rd_out[214]
  PIN rw0_rd_out[215]
    DIRECTION OUTPUT ;
    USE SIGNAL ;
    SHAPE ABUTMENT ;
    PORT
      LAYER M4_m ;
      RECT 69.318 10.896 69.342 10.92 ;
    END
  END rw0_rd_out[215]
  PIN rw0_rd_out[216]
    DIRECTION OUTPUT ;
    USE SIGNAL ;
    SHAPE ABUTMENT ;
    PORT
      LAYER M4_m ;
      RECT 69.318 10.944 69.342 10.968 ;
    END
  END rw0_rd_out[216]
  PIN rw0_rd_out[217]
    DIRECTION OUTPUT ;
    USE SIGNAL ;
    SHAPE ABUTMENT ;
    PORT
      LAYER M4_m ;
      RECT 69.318 10.992 69.342 11.016 ;
    END
  END rw0_rd_out[217]
  PIN rw0_rd_out[218]
    DIRECTION OUTPUT ;
    USE SIGNAL ;
    SHAPE ABUTMENT ;
    PORT
      LAYER M4_m ;
      RECT 69.318 11.04 69.342 11.064 ;
    END
  END rw0_rd_out[218]
  PIN rw0_rd_out[219]
    DIRECTION OUTPUT ;
    USE SIGNAL ;
    SHAPE ABUTMENT ;
    PORT
      LAYER M4_m ;
      RECT 69.318 11.088 69.342 11.112 ;
    END
  END rw0_rd_out[219]
  PIN rw0_rd_out[220]
    DIRECTION OUTPUT ;
    USE SIGNAL ;
    SHAPE ABUTMENT ;
    PORT
      LAYER M4_m ;
      RECT 69.318 11.136 69.342 11.16 ;
    END
  END rw0_rd_out[220]
  PIN rw0_rd_out[221]
    DIRECTION OUTPUT ;
    USE SIGNAL ;
    SHAPE ABUTMENT ;
    PORT
      LAYER M4_m ;
      RECT 69.318 11.184 69.342 11.208 ;
    END
  END rw0_rd_out[221]
  PIN rw0_rd_out[222]
    DIRECTION OUTPUT ;
    USE SIGNAL ;
    SHAPE ABUTMENT ;
    PORT
      LAYER M4_m ;
      RECT 69.318 11.232 69.342 11.256 ;
    END
  END rw0_rd_out[222]
  PIN rw0_rd_out[223]
    DIRECTION OUTPUT ;
    USE SIGNAL ;
    SHAPE ABUTMENT ;
    PORT
      LAYER M4_m ;
      RECT 69.318 11.28 69.342 11.304 ;
    END
  END rw0_rd_out[223]
  PIN rw0_rd_out[224]
    DIRECTION OUTPUT ;
    USE SIGNAL ;
    SHAPE ABUTMENT ;
    PORT
      LAYER M4_m ;
      RECT 69.318 11.328 69.342 11.352 ;
    END
  END rw0_rd_out[224]
  PIN rw0_rd_out[225]
    DIRECTION OUTPUT ;
    USE SIGNAL ;
    SHAPE ABUTMENT ;
    PORT
      LAYER M4_m ;
      RECT 69.318 11.376 69.342 11.4 ;
    END
  END rw0_rd_out[225]
  PIN rw0_rd_out[226]
    DIRECTION OUTPUT ;
    USE SIGNAL ;
    SHAPE ABUTMENT ;
    PORT
      LAYER M4_m ;
      RECT 69.318 11.424 69.342 11.448 ;
    END
  END rw0_rd_out[226]
  PIN rw0_rd_out[227]
    DIRECTION OUTPUT ;
    USE SIGNAL ;
    SHAPE ABUTMENT ;
    PORT
      LAYER M4_m ;
      RECT 69.318 11.472 69.342 11.496 ;
    END
  END rw0_rd_out[227]
  PIN rw0_rd_out[228]
    DIRECTION OUTPUT ;
    USE SIGNAL ;
    SHAPE ABUTMENT ;
    PORT
      LAYER M4_m ;
      RECT 69.318 11.52 69.342 11.544 ;
    END
  END rw0_rd_out[228]
  PIN rw0_rd_out[229]
    DIRECTION OUTPUT ;
    USE SIGNAL ;
    SHAPE ABUTMENT ;
    PORT
      LAYER M4_m ;
      RECT 69.318 11.568 69.342 11.592 ;
    END
  END rw0_rd_out[229]
  PIN rw0_rd_out[230]
    DIRECTION OUTPUT ;
    USE SIGNAL ;
    SHAPE ABUTMENT ;
    PORT
      LAYER M4_m ;
      RECT 69.318 11.616 69.342 11.64 ;
    END
  END rw0_rd_out[230]
  PIN rw0_rd_out[231]
    DIRECTION OUTPUT ;
    USE SIGNAL ;
    SHAPE ABUTMENT ;
    PORT
      LAYER M4_m ;
      RECT 69.318 11.664 69.342 11.688 ;
    END
  END rw0_rd_out[231]
  PIN rw0_rd_out[232]
    DIRECTION OUTPUT ;
    USE SIGNAL ;
    SHAPE ABUTMENT ;
    PORT
      LAYER M4_m ;
      RECT 69.318 11.712 69.342 11.736 ;
    END
  END rw0_rd_out[232]
  PIN rw0_rd_out[233]
    DIRECTION OUTPUT ;
    USE SIGNAL ;
    SHAPE ABUTMENT ;
    PORT
      LAYER M4_m ;
      RECT 69.318 11.76 69.342 11.784 ;
    END
  END rw0_rd_out[233]
  PIN rw0_rd_out[234]
    DIRECTION OUTPUT ;
    USE SIGNAL ;
    SHAPE ABUTMENT ;
    PORT
      LAYER M4_m ;
      RECT 69.318 11.808 69.342 11.832 ;
    END
  END rw0_rd_out[234]
  PIN rw0_rd_out[235]
    DIRECTION OUTPUT ;
    USE SIGNAL ;
    SHAPE ABUTMENT ;
    PORT
      LAYER M4_m ;
      RECT 69.318 11.856 69.342 11.88 ;
    END
  END rw0_rd_out[235]
  PIN rw0_rd_out[236]
    DIRECTION OUTPUT ;
    USE SIGNAL ;
    SHAPE ABUTMENT ;
    PORT
      LAYER M4_m ;
      RECT 69.318 11.904 69.342 11.928 ;
    END
  END rw0_rd_out[236]
  PIN rw0_rd_out[237]
    DIRECTION OUTPUT ;
    USE SIGNAL ;
    SHAPE ABUTMENT ;
    PORT
      LAYER M4_m ;
      RECT 69.318 11.952 69.342 11.976 ;
    END
  END rw0_rd_out[237]
  PIN rw0_rd_out[238]
    DIRECTION OUTPUT ;
    USE SIGNAL ;
    SHAPE ABUTMENT ;
    PORT
      LAYER M4_m ;
      RECT 69.318 12 69.342 12.024 ;
    END
  END rw0_rd_out[238]
  PIN rw0_rd_out[239]
    DIRECTION OUTPUT ;
    USE SIGNAL ;
    SHAPE ABUTMENT ;
    PORT
      LAYER M4_m ;
      RECT 69.318 12.048 69.342 12.072 ;
    END
  END rw0_rd_out[239]
  PIN rw0_rd_out[240]
    DIRECTION OUTPUT ;
    USE SIGNAL ;
    SHAPE ABUTMENT ;
    PORT
      LAYER M4_m ;
      RECT 69.318 12.096 69.342 12.12 ;
    END
  END rw0_rd_out[240]
  PIN rw0_rd_out[241]
    DIRECTION OUTPUT ;
    USE SIGNAL ;
    SHAPE ABUTMENT ;
    PORT
      LAYER M4_m ;
      RECT 69.318 12.144 69.342 12.168 ;
    END
  END rw0_rd_out[241]
  PIN rw0_rd_out[242]
    DIRECTION OUTPUT ;
    USE SIGNAL ;
    SHAPE ABUTMENT ;
    PORT
      LAYER M4_m ;
      RECT 69.318 12.192 69.342 12.216 ;
    END
  END rw0_rd_out[242]
  PIN rw0_rd_out[243]
    DIRECTION OUTPUT ;
    USE SIGNAL ;
    SHAPE ABUTMENT ;
    PORT
      LAYER M4_m ;
      RECT 69.318 12.24 69.342 12.264 ;
    END
  END rw0_rd_out[243]
  PIN rw0_rd_out[244]
    DIRECTION OUTPUT ;
    USE SIGNAL ;
    SHAPE ABUTMENT ;
    PORT
      LAYER M4_m ;
      RECT 69.318 12.288 69.342 12.312 ;
    END
  END rw0_rd_out[244]
  PIN rw0_rd_out[245]
    DIRECTION OUTPUT ;
    USE SIGNAL ;
    SHAPE ABUTMENT ;
    PORT
      LAYER M4_m ;
      RECT 69.318 12.336 69.342 12.36 ;
    END
  END rw0_rd_out[245]
  PIN rw0_rd_out[246]
    DIRECTION OUTPUT ;
    USE SIGNAL ;
    SHAPE ABUTMENT ;
    PORT
      LAYER M4_m ;
      RECT 69.318 12.384 69.342 12.408 ;
    END
  END rw0_rd_out[246]
  PIN rw0_rd_out[247]
    DIRECTION OUTPUT ;
    USE SIGNAL ;
    SHAPE ABUTMENT ;
    PORT
      LAYER M4_m ;
      RECT 69.318 12.432 69.342 12.456 ;
    END
  END rw0_rd_out[247]
  PIN rw0_rd_out[248]
    DIRECTION OUTPUT ;
    USE SIGNAL ;
    SHAPE ABUTMENT ;
    PORT
      LAYER M4_m ;
      RECT 69.318 12.48 69.342 12.504 ;
    END
  END rw0_rd_out[248]
  PIN rw0_rd_out[249]
    DIRECTION OUTPUT ;
    USE SIGNAL ;
    SHAPE ABUTMENT ;
    PORT
      LAYER M4_m ;
      RECT 69.318 12.528 69.342 12.552 ;
    END
  END rw0_rd_out[249]
  PIN rw0_rd_out[250]
    DIRECTION OUTPUT ;
    USE SIGNAL ;
    SHAPE ABUTMENT ;
    PORT
      LAYER M4_m ;
      RECT 69.318 12.576 69.342 12.6 ;
    END
  END rw0_rd_out[250]
  PIN rw0_rd_out[251]
    DIRECTION OUTPUT ;
    USE SIGNAL ;
    SHAPE ABUTMENT ;
    PORT
      LAYER M4_m ;
      RECT 69.318 12.624 69.342 12.648 ;
    END
  END rw0_rd_out[251]
  PIN rw0_rd_out[252]
    DIRECTION OUTPUT ;
    USE SIGNAL ;
    SHAPE ABUTMENT ;
    PORT
      LAYER M4_m ;
      RECT 69.318 12.672 69.342 12.696 ;
    END
  END rw0_rd_out[252]
  PIN rw0_rd_out[253]
    DIRECTION OUTPUT ;
    USE SIGNAL ;
    SHAPE ABUTMENT ;
    PORT
      LAYER M4_m ;
      RECT 69.318 12.72 69.342 12.744 ;
    END
  END rw0_rd_out[253]
  PIN rw0_rd_out[254]
    DIRECTION OUTPUT ;
    USE SIGNAL ;
    SHAPE ABUTMENT ;
    PORT
      LAYER M4_m ;
      RECT 69.318 12.768 69.342 12.792 ;
    END
  END rw0_rd_out[254]
  PIN rw0_rd_out[255]
    DIRECTION OUTPUT ;
    USE SIGNAL ;
    SHAPE ABUTMENT ;
    PORT
      LAYER M4_m ;
      RECT 69.318 12.816 69.342 12.84 ;
    END
  END rw0_rd_out[255]
  PIN rw0_addr_in[0]
    DIRECTION INPUT ;
    USE SIGNAL ;
    SHAPE ABUTMENT ;
    PORT
      LAYER M4_m ;
      RECT 69.318 12.864 69.342 12.888 ;
    END
  END rw0_addr_in[0]
  PIN rw0_addr_in[1]
    DIRECTION INPUT ;
    USE SIGNAL ;
    SHAPE ABUTMENT ;
    PORT
      LAYER M4_m ;
      RECT 69.318 12.912 69.342 12.936 ;
    END
  END rw0_addr_in[1]
  PIN rw0_addr_in[2]
    DIRECTION INPUT ;
    USE SIGNAL ;
    SHAPE ABUTMENT ;
    PORT
      LAYER M4_m ;
      RECT 69.318 12.96 69.342 12.984 ;
    END
  END rw0_addr_in[2]
  PIN rw0_addr_in[3]
    DIRECTION INPUT ;
    USE SIGNAL ;
    SHAPE ABUTMENT ;
    PORT
      LAYER M4_m ;
      RECT 69.318 13.008 69.342 13.032 ;
    END
  END rw0_addr_in[3]
  PIN rw0_addr_in[4]
    DIRECTION INPUT ;
    USE SIGNAL ;
    SHAPE ABUTMENT ;
    PORT
      LAYER M4_m ;
      RECT 69.318 13.056 69.342 13.08 ;
    END
  END rw0_addr_in[4]
  PIN rw0_addr_in[5]
    DIRECTION INPUT ;
    USE SIGNAL ;
    SHAPE ABUTMENT ;
    PORT
      LAYER M4_m ;
      RECT 69.318 13.104 69.342 13.128 ;
    END
  END rw0_addr_in[5]
  PIN rw0_addr_in[6]
    DIRECTION INPUT ;
    USE SIGNAL ;
    SHAPE ABUTMENT ;
    PORT
      LAYER M4_m ;
      RECT 69.318 13.152 69.342 13.176 ;
    END
  END rw0_addr_in[6]
  PIN rw0_we_in
    DIRECTION INPUT ;
    USE SIGNAL ;
    SHAPE ABUTMENT ;
    PORT
      LAYER M4_m ;
      RECT 69.318 13.2 69.342 13.224 ;
    END
  END rw0_we_in
  PIN rw0_ce_in
    DIRECTION INPUT ;
    USE SIGNAL ;
    SHAPE ABUTMENT ;
    PORT
      LAYER M4_m ;
      RECT 69.318 13.248 69.342 13.272 ;
    END
  END rw0_ce_in
  PIN rw0_clk
    DIRECTION INPUT ;
    USE SIGNAL ;
    SHAPE ABUTMENT ;
    PORT
      LAYER M4_m ;
      RECT 69.318 13.296 69.342 13.32 ;
    END
  END rw0_clk
  PIN VSS
    DIRECTION INOUT ;
    USE GROUND ;
    PORT
      LAYER M4_m ;
      RECT 0.048 0 69.294 0.096 ;
      RECT 0.048 0.768 69.294 0.864 ;
      RECT 0.048 1.536 69.294 1.632 ;
      RECT 0.048 2.304 69.294 2.4 ;
      RECT 0.048 3.072 69.294 3.168 ;
      RECT 0.048 3.84 69.294 3.936 ;
      RECT 0.048 4.608 69.294 4.704 ;
      RECT 0.048 5.376 69.294 5.472 ;
      RECT 0.048 6.144 69.294 6.24 ;
      RECT 0.048 6.912 69.294 7.008 ;
      RECT 0.048 7.68 69.294 7.776 ;
      RECT 0.048 8.448 69.294 8.544 ;
      RECT 0.048 9.216 69.294 9.312 ;
      RECT 0.048 9.984 69.294 10.08 ;
      RECT 0.048 10.752 69.294 10.848 ;
      RECT 0.048 11.52 69.294 11.616 ;
      RECT 0.048 12.288 69.294 12.384 ;
      RECT 0.048 13.056 69.294 13.152 ;
      RECT 0.048 13.824 69.294 13.92 ;
      RECT 0.048 14.592 69.294 14.688 ;
      RECT 0.048 15.36 69.294 15.456 ;
      RECT 0.048 16.128 69.294 16.224 ;
      RECT 0.048 16.896 69.294 16.992 ;
      RECT 0.048 17.664 69.294 17.76 ;
      RECT 0.048 18.432 69.294 18.528 ;
      RECT 0.048 19.2 69.294 19.296 ;
      RECT 0.048 19.968 69.294 20.064 ;
      RECT 0.048 20.736 69.294 20.832 ;
      RECT 0.048 21.504 69.294 21.6 ;
    END
  END VSS
  PIN VDD
    DIRECTION INOUT ;
    USE POWER ;
    PORT
      LAYER M4_m ;
      RECT 0.048 0.384 69.294 0.48 ;
      RECT 0.048 1.152 69.294 1.248 ;
      RECT 0.048 1.92 69.294 2.016 ;
      RECT 0.048 2.688 69.294 2.784 ;
      RECT 0.048 3.456 69.294 3.552 ;
      RECT 0.048 4.224 69.294 4.32 ;
      RECT 0.048 4.992 69.294 5.088 ;
      RECT 0.048 5.76 69.294 5.856 ;
      RECT 0.048 6.528 69.294 6.624 ;
      RECT 0.048 7.296 69.294 7.392 ;
      RECT 0.048 8.064 69.294 8.16 ;
      RECT 0.048 8.832 69.294 8.928 ;
      RECT 0.048 9.6 69.294 9.696 ;
      RECT 0.048 10.368 69.294 10.464 ;
      RECT 0.048 11.136 69.294 11.232 ;
      RECT 0.048 11.904 69.294 12 ;
      RECT 0.048 12.672 69.294 12.768 ;
      RECT 0.048 13.44 69.294 13.536 ;
      RECT 0.048 14.208 69.294 14.304 ;
      RECT 0.048 14.976 69.294 15.072 ;
      RECT 0.048 15.744 69.294 15.84 ;
      RECT 0.048 16.512 69.294 16.608 ;
      RECT 0.048 17.28 69.294 17.376 ;
      RECT 0.048 18.048 69.294 18.144 ;
      RECT 0.048 18.816 69.294 18.912 ;
      RECT 0.048 19.584 69.294 19.68 ;
      RECT 0.048 20.352 69.294 20.448 ;
      RECT 0.048 21.12 69.294 21.216 ;
    END
  END VDD
  OBS
    LAYER M1_m ;
    RECT 0 0 69.342 21.67 ;
    LAYER M2_m ;
    RECT 0 0 69.342 21.67 ;
    LAYER M3_m ;
    RECT 0 0 69.342 21.67 ;
  END
END ht_asap7_mempoolgroup_256x128_upper

END LIBRARY
